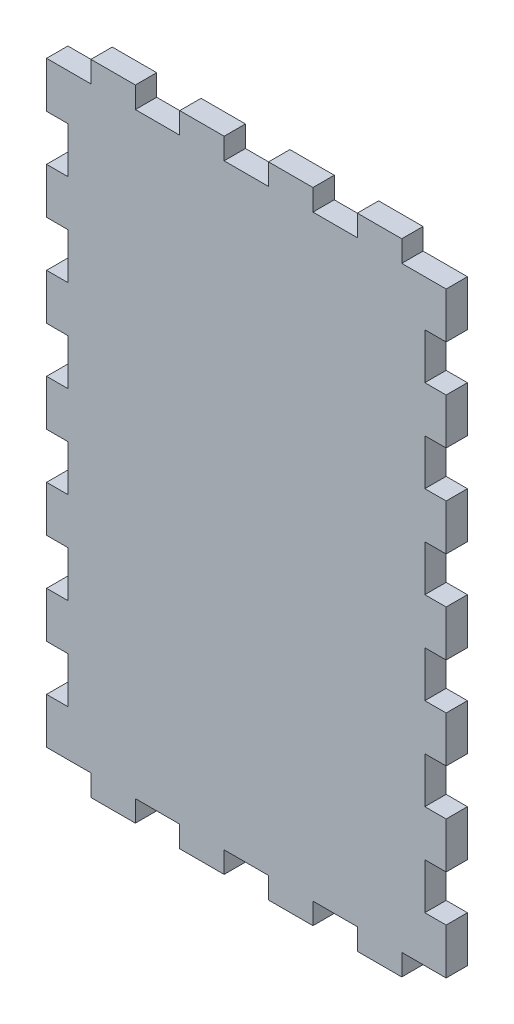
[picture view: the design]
ISO-10303-21;
HEADER;
FILE_DESCRIPTION(('STEP AP214'),'2;1');
FILE_NAME('part.step','',(''),(''),'','','');
FILE_SCHEMA(('AUTOMOTIVE_DESIGN { 1 0 10303 214 1 1 1 1 }'));
ENDSEC;
DATA;
#1=APPLICATION_CONTEXT('core data for automotive mechanical design processes');
#2=APPLICATION_PROTOCOL_DEFINITION('international standard','automotive_design',2000,#1);
#3=PRODUCT_CONTEXT('',#1,'mechanical');
#4=PRODUCT('Part','Part','',(#3));
#5=PRODUCT_RELATED_PRODUCT_CATEGORY('part','',(#4));
#6=PRODUCT_DEFINITION_FORMATION('','',#4);
#7=PRODUCT_DEFINITION_CONTEXT('part definition',#1,'design');
#8=PRODUCT_DEFINITION('design','',#6,#7);
#9=PRODUCT_DEFINITION_SHAPE('','',#8);
#10=(LENGTH_UNIT() NAMED_UNIT(*) SI_UNIT(.MILLI.,.METRE.));
#11=(NAMED_UNIT(*) PLANE_ANGLE_UNIT() SI_UNIT($,.RADIAN.));
#12=(NAMED_UNIT(*) SI_UNIT($,.STERADIAN.) SOLID_ANGLE_UNIT());
#13=UNCERTAINTY_MEASURE_WITH_UNIT(LENGTH_MEASURE(1.E-05),#10,'distance_accuracy_value','');
#14=(GEOMETRIC_REPRESENTATION_CONTEXT(3) GLOBAL_UNCERTAINTY_ASSIGNED_CONTEXT((#13)) GLOBAL_UNIT_ASSIGNED_CONTEXT((#10,
#11,#12)) REPRESENTATION_CONTEXT('',''));
#15=CARTESIAN_POINT('',(0.,0.,0.));
#16=DIRECTION('',(0.,0.,1.));
#17=DIRECTION('',(1.,0.,0.));
#18=AXIS2_PLACEMENT_3D('',#15,#16,#17);
#19=CARTESIAN_POINT('',(269.67,0.,4.));
#20=DIRECTION('',(-1.,0.,0.));
#21=DIRECTION('',(0.,0.,1.));
#22=AXIS2_PLACEMENT_3D('',#19,#20,#21);
#23=PLANE('',#22);
#24=DIRECTION('',(0.,1.,0.));
#25=VECTOR('',#24,1.);
#26=CARTESIAN_POINT('',(269.67,0.,0.));
#27=LINE('',#26,#25);
#28=CARTESIAN_POINT('',(269.67,79.,0.));
#29=VERTEX_POINT('',#28);
#30=CARTESIAN_POINT('',(269.67,83.,0.));
#31=VERTEX_POINT('',#30);
#32=EDGE_CURVE('E585',#29,#31,#27,.T.);
#33=ORIENTED_EDGE('',*,*,#32,.T.);
#34=DIRECTION('',(0.,0.,-1.));
#35=VECTOR('',#34,1.);
#36=CARTESIAN_POINT('',(269.67,83.,4.));
#37=LINE('',#36,#35);
#38=CARTESIAN_POINT('',(269.67,83.,4.));
#39=VERTEX_POINT('',#38);
#40=EDGE_CURVE('E11',#39,#31,#37,.T.);
#41=ORIENTED_EDGE('',*,*,#40,.F.);
#42=DIRECTION('',(0.,1.,0.));
#43=VECTOR('',#42,1.);
#44=CARTESIAN_POINT('',(269.67,0.,4.));
#45=LINE('',#44,#43);
#46=CARTESIAN_POINT('',(269.67,79.,4.));
#47=VERTEX_POINT('',#46);
#48=EDGE_CURVE('E751',#47,#39,#45,.T.);
#49=ORIENTED_EDGE('',*,*,#48,.F.);
#50=DIRECTION('',(0.,0.,-1.));
#51=VECTOR('',#50,1.);
#52=CARTESIAN_POINT('',(269.67,79.,4.));
#53=LINE('',#52,#51);
#54=EDGE_CURVE('E581',#47,#29,#53,.T.);
#55=ORIENTED_EDGE('',*,*,#54,.T.);
#56=EDGE_LOOP('',(#33,#41,#49,#55));
#57=FACE_BOUND('',#56,.T.);
#58=ADVANCED_FACE('F33',(#57),#23,.F.);
#59=CARTESIAN_POINT('',(0.,83.,4.));
#60=DIRECTION('',(0.,1.,0.));
#61=DIRECTION('',(0.,0.,1.));
#62=AXIS2_PLACEMENT_3D('',#59,#60,#61);
#63=PLANE('',#62);
#64=DIRECTION('',(1.,0.,0.));
#65=VECTOR('',#64,1.);
#66=CARTESIAN_POINT('',(0.,83.,0.));
#67=LINE('',#66,#65);
#68=CARTESIAN_POINT('',(278.,83.,0.));
#69=VERTEX_POINT('',#68);
#70=EDGE_CURVE('E588',#31,#69,#67,.T.);
#71=ORIENTED_EDGE('',*,*,#70,.T.);
#72=DIRECTION('',(0.,0.,-1.));
#73=VECTOR('',#72,1.);
#74=CARTESIAN_POINT('',(278.,83.,4.));
#75=LINE('',#74,#73);
#76=CARTESIAN_POINT('',(278.,83.,4.));
#77=VERTEX_POINT('',#76);
#78=EDGE_CURVE('E41',#77,#69,#75,.T.);
#79=ORIENTED_EDGE('',*,*,#78,.F.);
#80=DIRECTION('',(1.,0.,0.));
#81=VECTOR('',#80,1.);
#82=CARTESIAN_POINT('',(0.,83.,4.));
#83=LINE('',#82,#81);
#84=EDGE_CURVE('E320',#39,#77,#83,.T.);
#85=ORIENTED_EDGE('',*,*,#84,.F.);
#86=ORIENTED_EDGE('',*,*,#40,.T.);
#87=EDGE_LOOP('',(#71,#79,#85,#86));
#88=FACE_BOUND('',#87,.T.);
#89=ADVANCED_FACE('F1189',(#88),#63,.F.);
#90=CARTESIAN_POINT('',(278.,0.,4.));
#91=DIRECTION('',(-1.,0.,0.));
#92=DIRECTION('',(0.,0.,1.));
#93=AXIS2_PLACEMENT_3D('',#90,#91,#92);
#94=PLANE('',#93);
#95=DIRECTION('',(0.,1.,0.));
#96=VECTOR('',#95,1.);
#97=CARTESIAN_POINT('',(278.,0.,0.));
#98=LINE('',#97,#96);
#99=CARTESIAN_POINT('',(278.,91.61,0.));
#100=VERTEX_POINT('',#99);
#101=EDGE_CURVE('E590',#69,#100,#98,.T.);
#102=ORIENTED_EDGE('',*,*,#101,.T.);
#103=DIRECTION('',(0.,0.,-1.));
#104=VECTOR('',#103,1.);
#105=CARTESIAN_POINT('',(278.,91.61,4.));
#106=LINE('',#105,#104);
#107=CARTESIAN_POINT('',(278.,91.61,4.));
#108=VERTEX_POINT('',#107);
#109=EDGE_CURVE('E986',#108,#100,#106,.T.);
#110=ORIENTED_EDGE('',*,*,#109,.F.);
#111=DIRECTION('',(0.,1.,0.));
#112=VECTOR('',#111,1.);
#113=CARTESIAN_POINT('',(278.,0.,4.));
#114=LINE('',#113,#112);
#115=EDGE_CURVE('E994',#77,#108,#114,.T.);
#116=ORIENTED_EDGE('',*,*,#115,.F.);
#117=ORIENTED_EDGE('',*,*,#78,.T.);
#118=EDGE_LOOP('',(#102,#110,#116,#117));
#119=FACE_BOUND('',#118,.T.);
#120=ADVANCED_FACE('F992',(#119),#94,.F.);
#121=CARTESIAN_POINT('',(0.,91.61,4.));
#122=DIRECTION('',(0.,-1.,0.));
#123=DIRECTION('',(0.,0.,-1.));
#124=AXIS2_PLACEMENT_3D('',#121,#122,#123);
#125=PLANE('',#124);
#126=DIRECTION('',(-1.,0.,0.));
#127=VECTOR('',#126,1.);
#128=CARTESIAN_POINT('',(0.,91.61,0.));
#129=LINE('',#128,#127);
#130=CARTESIAN_POINT('',(274.,91.61,0.));
#131=VERTEX_POINT('',#130);
#132=EDGE_CURVE('E592',#100,#131,#129,.T.);
#133=ORIENTED_EDGE('',*,*,#132,.T.);
#134=DIRECTION('',(0.,0.,-1.));
#135=VECTOR('',#134,1.);
#136=CARTESIAN_POINT('',(274.,91.61,4.));
#137=LINE('',#136,#135);
#138=CARTESIAN_POINT('',(274.,91.61,4.));
#139=VERTEX_POINT('',#138);
#140=EDGE_CURVE('E983',#139,#131,#137,.T.);
#141=ORIENTED_EDGE('',*,*,#140,.F.);
#142=DIRECTION('',(-1.,0.,0.));
#143=VECTOR('',#142,1.);
#144=CARTESIAN_POINT('',(0.,91.61,4.));
#145=LINE('',#144,#143);
#146=EDGE_CURVE('E1012',#108,#139,#145,.T.);
#147=ORIENTED_EDGE('',*,*,#146,.F.);
#148=ORIENTED_EDGE('',*,*,#109,.T.);
#149=EDGE_LOOP('',(#133,#141,#147,#148));
#150=FACE_BOUND('',#149,.T.);
#151=ADVANCED_FACE('F1003',(#150),#125,.F.);
#152=CARTESIAN_POINT('',(274.,0.,4.));
#153=DIRECTION('',(-1.,0.,0.));
#154=DIRECTION('',(0.,0.,1.));
#155=AXIS2_PLACEMENT_3D('',#152,#153,#154);
#156=PLANE('',#155);
#157=DIRECTION('',(0.,1.,0.));
#158=VECTOR('',#157,1.);
#159=CARTESIAN_POINT('',(274.,0.,0.));
#160=LINE('',#159,#158);
#161=CARTESIAN_POINT('',(274.,100.23,0.));
#162=VERTEX_POINT('',#161);
#163=EDGE_CURVE('E594',#131,#162,#160,.T.);
#164=ORIENTED_EDGE('',*,*,#163,.T.);
#165=DIRECTION('',(0.,0.,-1.));
#166=VECTOR('',#165,1.);
#167=CARTESIAN_POINT('',(274.,100.23,4.));
#168=LINE('',#167,#166);
#169=CARTESIAN_POINT('',(274.,100.23,4.));
#170=VERTEX_POINT('',#169);
#171=EDGE_CURVE('E980',#170,#162,#168,.T.);
#172=ORIENTED_EDGE('',*,*,#171,.F.);
#173=DIRECTION('',(0.,1.,0.));
#174=VECTOR('',#173,1.);
#175=CARTESIAN_POINT('',(274.,0.,4.));
#176=LINE('',#175,#174);
#177=EDGE_CURVE('E1009',#139,#170,#176,.T.);
#178=ORIENTED_EDGE('',*,*,#177,.F.);
#179=ORIENTED_EDGE('',*,*,#140,.T.);
#180=EDGE_LOOP('',(#164,#172,#178,#179));
#181=FACE_BOUND('',#180,.T.);
#182=ADVANCED_FACE('F1007',(#181),#156,.F.);
#183=CARTESIAN_POINT('',(0.,100.23,4.));
#184=DIRECTION('',(0.,1.,0.));
#185=DIRECTION('',(0.,0.,1.));
#186=AXIS2_PLACEMENT_3D('',#183,#184,#185);
#187=PLANE('',#186);
#188=DIRECTION('',(1.,0.,0.));
#189=VECTOR('',#188,1.);
#190=CARTESIAN_POINT('',(0.,100.23,0.));
#191=LINE('',#190,#189);
#192=CARTESIAN_POINT('',(278.,100.23,0.));
#193=VERTEX_POINT('',#192);
#194=EDGE_CURVE('E596',#162,#193,#191,.T.);
#195=ORIENTED_EDGE('',*,*,#194,.T.);
#196=DIRECTION('',(0.,0.,-1.));
#197=VECTOR('',#196,1.);
#198=CARTESIAN_POINT('',(278.,100.23,4.));
#199=LINE('',#198,#197);
#200=CARTESIAN_POINT('',(278.,100.23,4.));
#201=VERTEX_POINT('',#200);
#202=EDGE_CURVE('E977',#201,#193,#199,.T.);
#203=ORIENTED_EDGE('',*,*,#202,.F.);
#204=DIRECTION('',(1.,0.,0.));
#205=VECTOR('',#204,1.);
#206=CARTESIAN_POINT('',(0.,100.23,4.));
#207=LINE('',#206,#205);
#208=EDGE_CURVE('E1011',#170,#201,#207,.T.);
#209=ORIENTED_EDGE('',*,*,#208,.F.);
#210=ORIENTED_EDGE('',*,*,#171,.T.);
#211=EDGE_LOOP('',(#195,#203,#209,#210));
#212=FACE_BOUND('',#211,.T.);
#213=ADVANCED_FACE('F1202',(#212),#187,.F.);
#214=CARTESIAN_POINT('',(278.,0.,4.));
#215=DIRECTION('',(-1.,0.,0.));
#216=DIRECTION('',(0.,0.,1.));
#217=AXIS2_PLACEMENT_3D('',#214,#215,#216);
#218=PLANE('',#217);
#219=DIRECTION('',(0.,1.,0.));
#220=VECTOR('',#219,1.);
#221=CARTESIAN_POINT('',(278.,0.,0.));
#222=LINE('',#221,#220);
#223=CARTESIAN_POINT('',(278.,108.85,0.));
#224=VERTEX_POINT('',#223);
#225=EDGE_CURVE('E598',#193,#224,#222,.T.);
#226=ORIENTED_EDGE('',*,*,#225,.T.);
#227=DIRECTION('',(0.,0.,-1.));
#228=VECTOR('',#227,1.);
#229=CARTESIAN_POINT('',(278.,108.85,4.));
#230=LINE('',#229,#228);
#231=CARTESIAN_POINT('',(278.,108.85,4.));
#232=VERTEX_POINT('',#231);
#233=EDGE_CURVE('E974',#232,#224,#230,.T.);
#234=ORIENTED_EDGE('',*,*,#233,.F.);
#235=DIRECTION('',(0.,1.,0.));
#236=VECTOR('',#235,1.);
#237=CARTESIAN_POINT('',(278.,0.,4.));
#238=LINE('',#237,#236);
#239=EDGE_CURVE('E1014',#201,#232,#238,.T.);
#240=ORIENTED_EDGE('',*,*,#239,.F.);
#241=ORIENTED_EDGE('',*,*,#202,.T.);
#242=EDGE_LOOP('',(#226,#234,#240,#241));
#243=FACE_BOUND('',#242,.T.);
#244=ADVANCED_FACE('F1205',(#243),#218,.F.);
#245=CARTESIAN_POINT('',(0.,108.85,4.));
#246=DIRECTION('',(0.,-1.,0.));
#247=DIRECTION('',(0.,0.,-1.));
#248=AXIS2_PLACEMENT_3D('',#245,#246,#247);
#249=PLANE('',#248);
#250=DIRECTION('',(-1.,0.,0.));
#251=VECTOR('',#250,1.);
#252=CARTESIAN_POINT('',(0.,108.85,0.));
#253=LINE('',#252,#251);
#254=CARTESIAN_POINT('',(274.,108.85,0.));
#255=VERTEX_POINT('',#254);
#256=EDGE_CURVE('E600',#224,#255,#253,.T.);
#257=ORIENTED_EDGE('',*,*,#256,.T.);
#258=DIRECTION('',(0.,0.,-1.));
#259=VECTOR('',#258,1.);
#260=CARTESIAN_POINT('',(274.,108.85,4.));
#261=LINE('',#260,#259);
#262=CARTESIAN_POINT('',(274.,108.85,4.));
#263=VERTEX_POINT('',#262);
#264=EDGE_CURVE('E971',#263,#255,#261,.T.);
#265=ORIENTED_EDGE('',*,*,#264,.F.);
#266=DIRECTION('',(-1.,0.,0.));
#267=VECTOR('',#266,1.);
#268=CARTESIAN_POINT('',(0.,108.85,4.));
#269=LINE('',#268,#267);
#270=EDGE_CURVE('E1020',#232,#263,#269,.T.);
#271=ORIENTED_EDGE('',*,*,#270,.F.);
#272=ORIENTED_EDGE('',*,*,#233,.T.);
#273=EDGE_LOOP('',(#257,#265,#271,#272));
#274=FACE_BOUND('',#273,.T.);
#275=ADVANCED_FACE('F1209',(#274),#249,.F.);
#276=CARTESIAN_POINT('',(274.,0.,4.));
#277=DIRECTION('',(-1.,0.,0.));
#278=DIRECTION('',(0.,0.,1.));
#279=AXIS2_PLACEMENT_3D('',#276,#277,#278);
#280=PLANE('',#279);
#281=DIRECTION('',(0.,1.,0.));
#282=VECTOR('',#281,1.);
#283=CARTESIAN_POINT('',(274.,0.,0.));
#284=LINE('',#283,#282);
#285=CARTESIAN_POINT('',(274.,117.46,0.));
#286=VERTEX_POINT('',#285);
#287=EDGE_CURVE('E602',#255,#286,#284,.T.);
#288=ORIENTED_EDGE('',*,*,#287,.T.);
#289=DIRECTION('',(0.,0.,-1.));
#290=VECTOR('',#289,1.);
#291=CARTESIAN_POINT('',(274.,117.46,4.));
#292=LINE('',#291,#290);
#293=CARTESIAN_POINT('',(274.,117.46,4.));
#294=VERTEX_POINT('',#293);
#295=EDGE_CURVE('E968',#294,#286,#292,.T.);
#296=ORIENTED_EDGE('',*,*,#295,.F.);
#297=DIRECTION('',(0.,1.,0.));
#298=VECTOR('',#297,1.);
#299=CARTESIAN_POINT('',(274.,0.,4.));
#300=LINE('',#299,#298);
#301=EDGE_CURVE('E1022',#263,#294,#300,.T.);
#302=ORIENTED_EDGE('',*,*,#301,.F.);
#303=ORIENTED_EDGE('',*,*,#264,.T.);
#304=EDGE_LOOP('',(#288,#296,#302,#303));
#305=FACE_BOUND('',#304,.T.);
#306=ADVANCED_FACE('F1213',(#305),#280,.F.);
#307=CARTESIAN_POINT('',(0.,117.46,4.));
#308=DIRECTION('',(0.,1.,0.));
#309=DIRECTION('',(0.,0.,1.));
#310=AXIS2_PLACEMENT_3D('',#307,#308,#309);
#311=PLANE('',#310);
#312=DIRECTION('',(1.,0.,0.));
#313=VECTOR('',#312,1.);
#314=CARTESIAN_POINT('',(0.,117.46,0.));
#315=LINE('',#314,#313);
#316=CARTESIAN_POINT('',(278.,117.46,0.));
#317=VERTEX_POINT('',#316);
#318=EDGE_CURVE('E604',#286,#317,#315,.T.);
#319=ORIENTED_EDGE('',*,*,#318,.T.);
#320=DIRECTION('',(0.,0.,-1.));
#321=VECTOR('',#320,1.);
#322=CARTESIAN_POINT('',(278.,117.46,4.));
#323=LINE('',#322,#321);
#324=CARTESIAN_POINT('',(278.,117.46,4.));
#325=VERTEX_POINT('',#324);
#326=EDGE_CURVE('E965',#325,#317,#323,.T.);
#327=ORIENTED_EDGE('',*,*,#326,.F.);
#328=DIRECTION('',(1.,0.,0.));
#329=VECTOR('',#328,1.);
#330=CARTESIAN_POINT('',(0.,117.46,4.));
#331=LINE('',#330,#329);
#332=EDGE_CURVE('E1024',#294,#325,#331,.T.);
#333=ORIENTED_EDGE('',*,*,#332,.F.);
#334=ORIENTED_EDGE('',*,*,#295,.T.);
#335=EDGE_LOOP('',(#319,#327,#333,#334));
#336=FACE_BOUND('',#335,.T.);
#337=ADVANCED_FACE('F1217',(#336),#311,.F.);
#338=CARTESIAN_POINT('',(278.,0.,4.));
#339=DIRECTION('',(-1.,0.,0.));
#340=DIRECTION('',(0.,0.,1.));
#341=AXIS2_PLACEMENT_3D('',#338,#339,#340);
#342=PLANE('',#341);
#343=DIRECTION('',(0.,1.,0.));
#344=VECTOR('',#343,1.);
#345=CARTESIAN_POINT('',(278.,0.,0.));
#346=LINE('',#345,#344);
#347=CARTESIAN_POINT('',(278.,126.08,0.));
#348=VERTEX_POINT('',#347);
#349=EDGE_CURVE('E606',#317,#348,#346,.T.);
#350=ORIENTED_EDGE('',*,*,#349,.T.);
#351=DIRECTION('',(0.,0.,-1.));
#352=VECTOR('',#351,1.);
#353=CARTESIAN_POINT('',(278.,126.08,4.));
#354=LINE('',#353,#352);
#355=CARTESIAN_POINT('',(278.,126.08,4.));
#356=VERTEX_POINT('',#355);
#357=EDGE_CURVE('E962',#356,#348,#354,.T.);
#358=ORIENTED_EDGE('',*,*,#357,.F.);
#359=DIRECTION('',(0.,1.,0.));
#360=VECTOR('',#359,1.);
#361=CARTESIAN_POINT('',(278.,0.,4.));
#362=LINE('',#361,#360);
#363=EDGE_CURVE('E1026',#325,#356,#362,.T.);
#364=ORIENTED_EDGE('',*,*,#363,.F.);
#365=ORIENTED_EDGE('',*,*,#326,.T.);
#366=EDGE_LOOP('',(#350,#358,#364,#365));
#367=FACE_BOUND('',#366,.T.);
#368=ADVANCED_FACE('F1221',(#367),#342,.F.);
#369=CARTESIAN_POINT('',(0.,126.08,4.));
#370=DIRECTION('',(0.,-1.,0.));
#371=DIRECTION('',(0.,0.,-1.));
#372=AXIS2_PLACEMENT_3D('',#369,#370,#371);
#373=PLANE('',#372);
#374=DIRECTION('',(-1.,0.,0.));
#375=VECTOR('',#374,1.);
#376=CARTESIAN_POINT('',(0.,126.08,0.));
#377=LINE('',#376,#375);
#378=CARTESIAN_POINT('',(274.,126.08,0.));
#379=VERTEX_POINT('',#378);
#380=EDGE_CURVE('E608',#348,#379,#377,.T.);
#381=ORIENTED_EDGE('',*,*,#380,.T.);
#382=DIRECTION('',(0.,0.,-1.));
#383=VECTOR('',#382,1.);
#384=CARTESIAN_POINT('',(274.,126.08,4.));
#385=LINE('',#384,#383);
#386=CARTESIAN_POINT('',(274.,126.08,4.));
#387=VERTEX_POINT('',#386);
#388=EDGE_CURVE('E959',#387,#379,#385,.T.);
#389=ORIENTED_EDGE('',*,*,#388,.F.);
#390=DIRECTION('',(-1.,0.,0.));
#391=VECTOR('',#390,1.);
#392=CARTESIAN_POINT('',(0.,126.08,4.));
#393=LINE('',#392,#391);
#394=EDGE_CURVE('E1028',#356,#387,#393,.T.);
#395=ORIENTED_EDGE('',*,*,#394,.F.);
#396=ORIENTED_EDGE('',*,*,#357,.T.);
#397=EDGE_LOOP('',(#381,#389,#395,#396));
#398=FACE_BOUND('',#397,.T.);
#399=ADVANCED_FACE('F1225',(#398),#373,.F.);
#400=CARTESIAN_POINT('',(274.,0.,4.));
#401=DIRECTION('',(-1.,0.,0.));
#402=DIRECTION('',(0.,0.,1.));
#403=AXIS2_PLACEMENT_3D('',#400,#401,#402);
#404=PLANE('',#403);
#405=DIRECTION('',(0.,1.,0.));
#406=VECTOR('',#405,1.);
#407=CARTESIAN_POINT('',(274.,0.,0.));
#408=LINE('',#407,#406);
#409=CARTESIAN_POINT('',(274.,134.69,0.));
#410=VERTEX_POINT('',#409);
#411=EDGE_CURVE('E610',#379,#410,#408,.T.);
#412=ORIENTED_EDGE('',*,*,#411,.T.);
#413=DIRECTION('',(0.,0.,-1.));
#414=VECTOR('',#413,1.);
#415=CARTESIAN_POINT('',(274.,134.69,4.));
#416=LINE('',#415,#414);
#417=CARTESIAN_POINT('',(274.,134.69,4.));
#418=VERTEX_POINT('',#417);
#419=EDGE_CURVE('E956',#418,#410,#416,.T.);
#420=ORIENTED_EDGE('',*,*,#419,.F.);
#421=DIRECTION('',(0.,1.,0.));
#422=VECTOR('',#421,1.);
#423=CARTESIAN_POINT('',(274.,0.,4.));
#424=LINE('',#423,#422);
#425=EDGE_CURVE('E1030',#387,#418,#424,.T.);
#426=ORIENTED_EDGE('',*,*,#425,.F.);
#427=ORIENTED_EDGE('',*,*,#388,.T.);
#428=EDGE_LOOP('',(#412,#420,#426,#427));
#429=FACE_BOUND('',#428,.T.);
#430=ADVANCED_FACE('F1229',(#429),#404,.F.);
#431=CARTESIAN_POINT('',(0.,134.69,4.));
#432=DIRECTION('',(0.,1.,0.));
#433=DIRECTION('',(0.,0.,1.));
#434=AXIS2_PLACEMENT_3D('',#431,#432,#433);
#435=PLANE('',#434);
#436=DIRECTION('',(1.,0.,0.));
#437=VECTOR('',#436,1.);
#438=CARTESIAN_POINT('',(0.,134.69,0.));
#439=LINE('',#438,#437);
#440=CARTESIAN_POINT('',(278.,134.69,0.));
#441=VERTEX_POINT('',#440);
#442=EDGE_CURVE('E612',#410,#441,#439,.T.);
#443=ORIENTED_EDGE('',*,*,#442,.T.);
#444=DIRECTION('',(0.,0.,-1.));
#445=VECTOR('',#444,1.);
#446=CARTESIAN_POINT('',(278.,134.69,4.));
#447=LINE('',#446,#445);
#448=CARTESIAN_POINT('',(278.,134.69,4.));
#449=VERTEX_POINT('',#448);
#450=EDGE_CURVE('E953',#449,#441,#447,.T.);
#451=ORIENTED_EDGE('',*,*,#450,.F.);
#452=DIRECTION('',(1.,0.,0.));
#453=VECTOR('',#452,1.);
#454=CARTESIAN_POINT('',(0.,134.69,4.));
#455=LINE('',#454,#453);
#456=EDGE_CURVE('E1032',#418,#449,#455,.T.);
#457=ORIENTED_EDGE('',*,*,#456,.F.);
#458=ORIENTED_EDGE('',*,*,#419,.T.);
#459=EDGE_LOOP('',(#443,#451,#457,#458));
#460=FACE_BOUND('',#459,.T.);
#461=ADVANCED_FACE('F1233',(#460),#435,.F.);
#462=CARTESIAN_POINT('',(278.,0.,4.));
#463=DIRECTION('',(-1.,0.,0.));
#464=DIRECTION('',(0.,0.,1.));
#465=AXIS2_PLACEMENT_3D('',#462,#463,#464);
#466=PLANE('',#465);
#467=DIRECTION('',(0.,1.,0.));
#468=VECTOR('',#467,1.);
#469=CARTESIAN_POINT('',(278.,0.,0.));
#470=LINE('',#469,#468);
#471=CARTESIAN_POINT('',(278.,143.31,0.));
#472=VERTEX_POINT('',#471);
#473=EDGE_CURVE('E614',#441,#472,#470,.T.);
#474=ORIENTED_EDGE('',*,*,#473,.T.);
#475=DIRECTION('',(0.,0.,-1.));
#476=VECTOR('',#475,1.);
#477=CARTESIAN_POINT('',(278.,143.31,4.));
#478=LINE('',#477,#476);
#479=CARTESIAN_POINT('',(278.,143.31,4.));
#480=VERTEX_POINT('',#479);
#481=EDGE_CURVE('E950',#480,#472,#478,.T.);
#482=ORIENTED_EDGE('',*,*,#481,.F.);
#483=DIRECTION('',(0.,1.,0.));
#484=VECTOR('',#483,1.);
#485=CARTESIAN_POINT('',(278.,0.,4.));
#486=LINE('',#485,#484);
#487=EDGE_CURVE('E1034',#449,#480,#486,.T.);
#488=ORIENTED_EDGE('',*,*,#487,.F.);
#489=ORIENTED_EDGE('',*,*,#450,.T.);
#490=EDGE_LOOP('',(#474,#482,#488,#489));
#491=FACE_BOUND('',#490,.T.);
#492=ADVANCED_FACE('F1237',(#491),#466,.F.);
#493=CARTESIAN_POINT('',(0.,143.31,4.));
#494=DIRECTION('',(0.,-1.,0.));
#495=DIRECTION('',(0.,0.,-1.));
#496=AXIS2_PLACEMENT_3D('',#493,#494,#495);
#497=PLANE('',#496);
#498=DIRECTION('',(-1.,0.,0.));
#499=VECTOR('',#498,1.);
#500=CARTESIAN_POINT('',(0.,143.31,0.));
#501=LINE('',#500,#499);
#502=CARTESIAN_POINT('',(274.,143.31,0.));
#503=VERTEX_POINT('',#502);
#504=EDGE_CURVE('E616',#472,#503,#501,.T.);
#505=ORIENTED_EDGE('',*,*,#504,.T.);
#506=DIRECTION('',(0.,0.,-1.));
#507=VECTOR('',#506,1.);
#508=CARTESIAN_POINT('',(274.,143.31,4.));
#509=LINE('',#508,#507);
#510=CARTESIAN_POINT('',(274.,143.31,4.));
#511=VERTEX_POINT('',#510);
#512=EDGE_CURVE('E947',#511,#503,#509,.T.);
#513=ORIENTED_EDGE('',*,*,#512,.F.);
#514=DIRECTION('',(-1.,0.,0.));
#515=VECTOR('',#514,1.);
#516=CARTESIAN_POINT('',(0.,143.31,4.));
#517=LINE('',#516,#515);
#518=EDGE_CURVE('E1036',#480,#511,#517,.T.);
#519=ORIENTED_EDGE('',*,*,#518,.F.);
#520=ORIENTED_EDGE('',*,*,#481,.T.);
#521=EDGE_LOOP('',(#505,#513,#519,#520));
#522=FACE_BOUND('',#521,.T.);
#523=ADVANCED_FACE('F1241',(#522),#497,.F.);
#524=CARTESIAN_POINT('',(274.,0.,4.));
#525=DIRECTION('',(-1.,0.,0.));
#526=DIRECTION('',(0.,0.,1.));
#527=AXIS2_PLACEMENT_3D('',#524,#525,#526);
#528=PLANE('',#527);
#529=DIRECTION('',(0.,1.,0.));
#530=VECTOR('',#529,1.);
#531=CARTESIAN_POINT('',(274.,0.,0.));
#532=LINE('',#531,#530);
#533=CARTESIAN_POINT('',(274.,151.92,0.));
#534=VERTEX_POINT('',#533);
#535=EDGE_CURVE('E618',#503,#534,#532,.T.);
#536=ORIENTED_EDGE('',*,*,#535,.T.);
#537=DIRECTION('',(0.,0.,-1.));
#538=VECTOR('',#537,1.);
#539=CARTESIAN_POINT('',(274.,151.92,4.));
#540=LINE('',#539,#538);
#541=CARTESIAN_POINT('',(274.,151.92,4.));
#542=VERTEX_POINT('',#541);
#543=EDGE_CURVE('E944',#542,#534,#540,.T.);
#544=ORIENTED_EDGE('',*,*,#543,.F.);
#545=DIRECTION('',(0.,1.,0.));
#546=VECTOR('',#545,1.);
#547=CARTESIAN_POINT('',(274.,0.,4.));
#548=LINE('',#547,#546);
#549=EDGE_CURVE('E1038',#511,#542,#548,.T.);
#550=ORIENTED_EDGE('',*,*,#549,.F.);
#551=ORIENTED_EDGE('',*,*,#512,.T.);
#552=EDGE_LOOP('',(#536,#544,#550,#551));
#553=FACE_BOUND('',#552,.T.);
#554=ADVANCED_FACE('F1245',(#553),#528,.F.);
#555=CARTESIAN_POINT('',(0.,151.92,4.));
#556=DIRECTION('',(0.,1.,0.));
#557=DIRECTION('',(0.,0.,1.));
#558=AXIS2_PLACEMENT_3D('',#555,#556,#557);
#559=PLANE('',#558);
#560=DIRECTION('',(1.,0.,0.));
#561=VECTOR('',#560,1.);
#562=CARTESIAN_POINT('',(0.,151.92,0.));
#563=LINE('',#562,#561);
#564=CARTESIAN_POINT('',(278.,151.92,0.));
#565=VERTEX_POINT('',#564);
#566=EDGE_CURVE('E620',#534,#565,#563,.T.);
#567=ORIENTED_EDGE('',*,*,#566,.T.);
#568=DIRECTION('',(0.,0.,-1.));
#569=VECTOR('',#568,1.);
#570=CARTESIAN_POINT('',(278.,151.92,4.));
#571=LINE('',#570,#569);
#572=CARTESIAN_POINT('',(278.,151.92,4.));
#573=VERTEX_POINT('',#572);
#574=EDGE_CURVE('E941',#573,#565,#571,.T.);
#575=ORIENTED_EDGE('',*,*,#574,.F.);
#576=DIRECTION('',(1.,0.,0.));
#577=VECTOR('',#576,1.);
#578=CARTESIAN_POINT('',(0.,151.92,4.));
#579=LINE('',#578,#577);
#580=EDGE_CURVE('E1040',#542,#573,#579,.T.);
#581=ORIENTED_EDGE('',*,*,#580,.F.);
#582=ORIENTED_EDGE('',*,*,#543,.T.);
#583=EDGE_LOOP('',(#567,#575,#581,#582));
#584=FACE_BOUND('',#583,.T.);
#585=ADVANCED_FACE('F1249',(#584),#559,.F.);
#586=CARTESIAN_POINT('',(278.,0.,4.));
#587=DIRECTION('',(-1.,0.,0.));
#588=DIRECTION('',(0.,0.,1.));
#589=AXIS2_PLACEMENT_3D('',#586,#587,#588);
#590=PLANE('',#589);
#591=DIRECTION('',(0.,1.,0.));
#592=VECTOR('',#591,1.);
#593=CARTESIAN_POINT('',(278.,0.,0.));
#594=LINE('',#593,#592);
#595=CARTESIAN_POINT('',(278.,160.54,0.));
#596=VERTEX_POINT('',#595);
#597=EDGE_CURVE('E622',#565,#596,#594,.T.);
#598=ORIENTED_EDGE('',*,*,#597,.T.);
#599=DIRECTION('',(0.,0.,-1.));
#600=VECTOR('',#599,1.);
#601=CARTESIAN_POINT('',(278.,160.54,4.));
#602=LINE('',#601,#600);
#603=CARTESIAN_POINT('',(278.,160.54,4.));
#604=VERTEX_POINT('',#603);
#605=EDGE_CURVE('E938',#604,#596,#602,.T.);
#606=ORIENTED_EDGE('',*,*,#605,.F.);
#607=DIRECTION('',(0.,1.,0.));
#608=VECTOR('',#607,1.);
#609=CARTESIAN_POINT('',(278.,0.,4.));
#610=LINE('',#609,#608);
#611=EDGE_CURVE('E1042',#573,#604,#610,.T.);
#612=ORIENTED_EDGE('',*,*,#611,.F.);
#613=ORIENTED_EDGE('',*,*,#574,.T.);
#614=EDGE_LOOP('',(#598,#606,#612,#613));
#615=FACE_BOUND('',#614,.T.);
#616=ADVANCED_FACE('F1253',(#615),#590,.F.);
#617=CARTESIAN_POINT('',(0.,160.54,4.));
#618=DIRECTION('',(0.,-1.,0.));
#619=DIRECTION('',(0.,0.,-1.));
#620=AXIS2_PLACEMENT_3D('',#617,#618,#619);
#621=PLANE('',#620);
#622=DIRECTION('',(-1.,0.,0.));
#623=VECTOR('',#622,1.);
#624=CARTESIAN_POINT('',(0.,160.54,0.));
#625=LINE('',#624,#623);
#626=CARTESIAN_POINT('',(274.,160.54,0.));
#627=VERTEX_POINT('',#626);
#628=EDGE_CURVE('E624',#596,#627,#625,.T.);
#629=ORIENTED_EDGE('',*,*,#628,.T.);
#630=DIRECTION('',(0.,0.,-1.));
#631=VECTOR('',#630,1.);
#632=CARTESIAN_POINT('',(274.,160.54,4.));
#633=LINE('',#632,#631);
#634=CARTESIAN_POINT('',(274.,160.54,4.));
#635=VERTEX_POINT('',#634);
#636=EDGE_CURVE('E935',#635,#627,#633,.T.);
#637=ORIENTED_EDGE('',*,*,#636,.F.);
#638=DIRECTION('',(-1.,0.,0.));
#639=VECTOR('',#638,1.);
#640=CARTESIAN_POINT('',(0.,160.54,4.));
#641=LINE('',#640,#639);
#642=EDGE_CURVE('E1044',#604,#635,#641,.T.);
#643=ORIENTED_EDGE('',*,*,#642,.F.);
#644=ORIENTED_EDGE('',*,*,#605,.T.);
#645=EDGE_LOOP('',(#629,#637,#643,#644));
#646=FACE_BOUND('',#645,.T.);
#647=ADVANCED_FACE('F1257',(#646),#621,.F.);
#648=CARTESIAN_POINT('',(274.,0.,4.));
#649=DIRECTION('',(-1.,0.,0.));
#650=DIRECTION('',(0.,0.,1.));
#651=AXIS2_PLACEMENT_3D('',#648,#649,#650);
#652=PLANE('',#651);
#653=DIRECTION('',(0.,1.,0.));
#654=VECTOR('',#653,1.);
#655=CARTESIAN_POINT('',(274.,0.,0.));
#656=LINE('',#655,#654);
#657=CARTESIAN_POINT('',(274.,169.15,0.));
#658=VERTEX_POINT('',#657);
#659=EDGE_CURVE('E626',#627,#658,#656,.T.);
#660=ORIENTED_EDGE('',*,*,#659,.T.);
#661=DIRECTION('',(0.,0.,-1.));
#662=VECTOR('',#661,1.);
#663=CARTESIAN_POINT('',(274.,169.15,4.));
#664=LINE('',#663,#662);
#665=CARTESIAN_POINT('',(274.,169.15,4.));
#666=VERTEX_POINT('',#665);
#667=EDGE_CURVE('E932',#666,#658,#664,.T.);
#668=ORIENTED_EDGE('',*,*,#667,.F.);
#669=DIRECTION('',(0.,1.,0.));
#670=VECTOR('',#669,1.);
#671=CARTESIAN_POINT('',(274.,0.,4.));
#672=LINE('',#671,#670);
#673=EDGE_CURVE('E1046',#635,#666,#672,.T.);
#674=ORIENTED_EDGE('',*,*,#673,.F.);
#675=ORIENTED_EDGE('',*,*,#636,.T.);
#676=EDGE_LOOP('',(#660,#668,#674,#675));
#677=FACE_BOUND('',#676,.T.);
#678=ADVANCED_FACE('F1261',(#677),#652,.F.);
#679=CARTESIAN_POINT('',(0.,169.15,4.));
#680=DIRECTION('',(0.,1.,0.));
#681=DIRECTION('',(0.,0.,1.));
#682=AXIS2_PLACEMENT_3D('',#679,#680,#681);
#683=PLANE('',#682);
#684=DIRECTION('',(1.,0.,0.));
#685=VECTOR('',#684,1.);
#686=CARTESIAN_POINT('',(0.,169.15,0.));
#687=LINE('',#686,#685);
#688=CARTESIAN_POINT('',(278.,169.15,0.));
#689=VERTEX_POINT('',#688);
#690=EDGE_CURVE('E628',#658,#689,#687,.T.);
#691=ORIENTED_EDGE('',*,*,#690,.T.);
#692=DIRECTION('',(0.,0.,-1.));
#693=VECTOR('',#692,1.);
#694=CARTESIAN_POINT('',(278.,169.15,4.));
#695=LINE('',#694,#693);
#696=CARTESIAN_POINT('',(278.,169.15,4.));
#697=VERTEX_POINT('',#696);
#698=EDGE_CURVE('E929',#697,#689,#695,.T.);
#699=ORIENTED_EDGE('',*,*,#698,.F.);
#700=DIRECTION('',(1.,0.,0.));
#701=VECTOR('',#700,1.);
#702=CARTESIAN_POINT('',(0.,169.15,4.));
#703=LINE('',#702,#701);
#704=EDGE_CURVE('E1048',#666,#697,#703,.T.);
#705=ORIENTED_EDGE('',*,*,#704,.F.);
#706=ORIENTED_EDGE('',*,*,#667,.T.);
#707=EDGE_LOOP('',(#691,#699,#705,#706));
#708=FACE_BOUND('',#707,.T.);
#709=ADVANCED_FACE('F1265',(#708),#683,.F.);
#710=CARTESIAN_POINT('',(278.,0.,4.));
#711=DIRECTION('',(-1.,0.,0.));
#712=DIRECTION('',(0.,0.,1.));
#713=AXIS2_PLACEMENT_3D('',#710,#711,#712);
#714=PLANE('',#713);
#715=DIRECTION('',(0.,1.,0.));
#716=VECTOR('',#715,1.);
#717=CARTESIAN_POINT('',(278.,0.,0.));
#718=LINE('',#717,#716);
#719=CARTESIAN_POINT('',(278.,177.77,0.));
#720=VERTEX_POINT('',#719);
#721=EDGE_CURVE('E630',#689,#720,#718,.T.);
#722=ORIENTED_EDGE('',*,*,#721,.T.);
#723=DIRECTION('',(0.,0.,-1.));
#724=VECTOR('',#723,1.);
#725=CARTESIAN_POINT('',(278.,177.77,4.));
#726=LINE('',#725,#724);
#727=CARTESIAN_POINT('',(278.,177.77,4.));
#728=VERTEX_POINT('',#727);
#729=EDGE_CURVE('E926',#728,#720,#726,.T.);
#730=ORIENTED_EDGE('',*,*,#729,.F.);
#731=DIRECTION('',(0.,1.,0.));
#732=VECTOR('',#731,1.);
#733=CARTESIAN_POINT('',(278.,0.,4.));
#734=LINE('',#733,#732);
#735=EDGE_CURVE('E1050',#697,#728,#734,.T.);
#736=ORIENTED_EDGE('',*,*,#735,.F.);
#737=ORIENTED_EDGE('',*,*,#698,.T.);
#738=EDGE_LOOP('',(#722,#730,#736,#737));
#739=FACE_BOUND('',#738,.T.);
#740=ADVANCED_FACE('F1269',(#739),#714,.F.);
#741=CARTESIAN_POINT('',(0.,177.77,4.));
#742=DIRECTION('',(0.,-1.,0.));
#743=DIRECTION('',(0.,0.,-1.));
#744=AXIS2_PLACEMENT_3D('',#741,#742,#743);
#745=PLANE('',#744);
#746=DIRECTION('',(-1.,0.,0.));
#747=VECTOR('',#746,1.);
#748=CARTESIAN_POINT('',(0.,177.77,0.));
#749=LINE('',#748,#747);
#750=CARTESIAN_POINT('',(274.,177.77,0.));
#751=VERTEX_POINT('',#750);
#752=EDGE_CURVE('E632',#720,#751,#749,.T.);
#753=ORIENTED_EDGE('',*,*,#752,.T.);
#754=DIRECTION('',(0.,0.,-1.));
#755=VECTOR('',#754,1.);
#756=CARTESIAN_POINT('',(274.,177.77,4.));
#757=LINE('',#756,#755);
#758=CARTESIAN_POINT('',(274.,177.77,4.));
#759=VERTEX_POINT('',#758);
#760=EDGE_CURVE('E923',#759,#751,#757,.T.);
#761=ORIENTED_EDGE('',*,*,#760,.F.);
#762=DIRECTION('',(-1.,0.,0.));
#763=VECTOR('',#762,1.);
#764=CARTESIAN_POINT('',(0.,177.77,4.));
#765=LINE('',#764,#763);
#766=EDGE_CURVE('E1052',#728,#759,#765,.T.);
#767=ORIENTED_EDGE('',*,*,#766,.F.);
#768=ORIENTED_EDGE('',*,*,#729,.T.);
#769=EDGE_LOOP('',(#753,#761,#767,#768));
#770=FACE_BOUND('',#769,.T.);
#771=ADVANCED_FACE('F1273',(#770),#745,.F.);
#772=CARTESIAN_POINT('',(274.,0.,4.));
#773=DIRECTION('',(-1.,0.,0.));
#774=DIRECTION('',(0.,0.,1.));
#775=AXIS2_PLACEMENT_3D('',#772,#773,#774);
#776=PLANE('',#775);
#777=DIRECTION('',(0.,1.,0.));
#778=VECTOR('',#777,1.);
#779=CARTESIAN_POINT('',(274.,0.,0.));
#780=LINE('',#779,#778);
#781=CARTESIAN_POINT('',(274.,186.38,0.));
#782=VERTEX_POINT('',#781);
#783=EDGE_CURVE('E634',#751,#782,#780,.T.);
#784=ORIENTED_EDGE('',*,*,#783,.T.);
#785=DIRECTION('',(0.,0.,-1.));
#786=VECTOR('',#785,1.);
#787=CARTESIAN_POINT('',(274.,186.38,4.));
#788=LINE('',#787,#786);
#789=CARTESIAN_POINT('',(274.,186.38,4.));
#790=VERTEX_POINT('',#789);
#791=EDGE_CURVE('E920',#790,#782,#788,.T.);
#792=ORIENTED_EDGE('',*,*,#791,.F.);
#793=DIRECTION('',(0.,1.,0.));
#794=VECTOR('',#793,1.);
#795=CARTESIAN_POINT('',(274.,0.,4.));
#796=LINE('',#795,#794);
#797=EDGE_CURVE('E1054',#759,#790,#796,.T.);
#798=ORIENTED_EDGE('',*,*,#797,.F.);
#799=ORIENTED_EDGE('',*,*,#760,.T.);
#800=EDGE_LOOP('',(#784,#792,#798,#799));
#801=FACE_BOUND('',#800,.T.);
#802=ADVANCED_FACE('F1277',(#801),#776,.F.);
#803=CARTESIAN_POINT('',(0.,186.38,4.));
#804=DIRECTION('',(0.,1.,0.));
#805=DIRECTION('',(0.,0.,1.));
#806=AXIS2_PLACEMENT_3D('',#803,#804,#805);
#807=PLANE('',#806);
#808=DIRECTION('',(1.,0.,0.));
#809=VECTOR('',#808,1.);
#810=CARTESIAN_POINT('',(0.,186.38,0.));
#811=LINE('',#810,#809);
#812=CARTESIAN_POINT('',(278.,186.38,0.));
#813=VERTEX_POINT('',#812);
#814=EDGE_CURVE('E636',#782,#813,#811,.T.);
#815=ORIENTED_EDGE('',*,*,#814,.T.);
#816=DIRECTION('',(0.,0.,-1.));
#817=VECTOR('',#816,1.);
#818=CARTESIAN_POINT('',(278.,186.38,4.));
#819=LINE('',#818,#817);
#820=CARTESIAN_POINT('',(278.,186.38,4.));
#821=VERTEX_POINT('',#820);
#822=EDGE_CURVE('E917',#821,#813,#819,.T.);
#823=ORIENTED_EDGE('',*,*,#822,.F.);
#824=DIRECTION('',(1.,0.,0.));
#825=VECTOR('',#824,1.);
#826=CARTESIAN_POINT('',(0.,186.38,4.));
#827=LINE('',#826,#825);
#828=EDGE_CURVE('E1056',#790,#821,#827,.T.);
#829=ORIENTED_EDGE('',*,*,#828,.F.);
#830=ORIENTED_EDGE('',*,*,#791,.T.);
#831=EDGE_LOOP('',(#815,#823,#829,#830));
#832=FACE_BOUND('',#831,.T.);
#833=ADVANCED_FACE('F1281',(#832),#807,.F.);
#834=CARTESIAN_POINT('',(278.,0.,4.));
#835=DIRECTION('',(-1.,0.,0.));
#836=DIRECTION('',(0.,0.,1.));
#837=AXIS2_PLACEMENT_3D('',#834,#835,#836);
#838=PLANE('',#837);
#839=DIRECTION('',(0.,1.,0.));
#840=VECTOR('',#839,1.);
#841=CARTESIAN_POINT('',(278.,0.,0.));
#842=LINE('',#841,#840);
#843=CARTESIAN_POINT('',(278.,195.,0.));
#844=VERTEX_POINT('',#843);
#845=EDGE_CURVE('E638',#813,#844,#842,.T.);
#846=ORIENTED_EDGE('',*,*,#845,.T.);
#847=DIRECTION('',(0.,0.,-1.));
#848=VECTOR('',#847,1.);
#849=CARTESIAN_POINT('',(278.,195.,4.));
#850=LINE('',#849,#848);
#851=CARTESIAN_POINT('',(278.,195.,4.));
#852=VERTEX_POINT('',#851);
#853=EDGE_CURVE('E914',#852,#844,#850,.T.);
#854=ORIENTED_EDGE('',*,*,#853,.F.);
#855=DIRECTION('',(0.,1.,0.));
#856=VECTOR('',#855,1.);
#857=CARTESIAN_POINT('',(278.,0.,4.));
#858=LINE('',#857,#856);
#859=EDGE_CURVE('E1058',#821,#852,#858,.T.);
#860=ORIENTED_EDGE('',*,*,#859,.F.);
#861=ORIENTED_EDGE('',*,*,#822,.T.);
#862=EDGE_LOOP('',(#846,#854,#860,#861));
#863=FACE_BOUND('',#862,.T.);
#864=ADVANCED_FACE('F1285',(#863),#838,.F.);
#865=CARTESIAN_POINT('',(0.,195.,4.));
#866=DIRECTION('',(0.,-1.,0.));
#867=DIRECTION('',(0.,0.,-1.));
#868=AXIS2_PLACEMENT_3D('',#865,#866,#867);
#869=PLANE('',#868);
#870=DIRECTION('',(-1.,0.,0.));
#871=VECTOR('',#870,1.);
#872=CARTESIAN_POINT('',(0.,195.,0.));
#873=LINE('',#872,#871);
#874=CARTESIAN_POINT('',(269.67,195.,0.));
#875=VERTEX_POINT('',#874);
#876=EDGE_CURVE('E640',#844,#875,#873,.T.);
#877=ORIENTED_EDGE('',*,*,#876,.T.);
#878=DIRECTION('',(0.,0.,-1.));
#879=VECTOR('',#878,1.);
#880=CARTESIAN_POINT('',(269.67,195.,4.));
#881=LINE('',#880,#879);
#882=CARTESIAN_POINT('',(269.67,195.,4.));
#883=VERTEX_POINT('',#882);
#884=EDGE_CURVE('E911',#883,#875,#881,.T.);
#885=ORIENTED_EDGE('',*,*,#884,.F.);
#886=DIRECTION('',(-1.,0.,0.));
#887=VECTOR('',#886,1.);
#888=CARTESIAN_POINT('',(0.,195.,4.));
#889=LINE('',#888,#887);
#890=EDGE_CURVE('E1060',#852,#883,#889,.T.);
#891=ORIENTED_EDGE('',*,*,#890,.F.);
#892=ORIENTED_EDGE('',*,*,#853,.T.);
#893=EDGE_LOOP('',(#877,#885,#891,#892));
#894=FACE_BOUND('',#893,.T.);
#895=ADVANCED_FACE('F1289',(#894),#869,.F.);
#896=CARTESIAN_POINT('',(269.67,0.,4.));
#897=DIRECTION('',(-1.,0.,0.));
#898=DIRECTION('',(0.,0.,1.));
#899=AXIS2_PLACEMENT_3D('',#896,#897,#898);
#900=PLANE('',#899);
#901=DIRECTION('',(0.,1.,0.));
#902=VECTOR('',#901,1.);
#903=CARTESIAN_POINT('',(269.67,0.,0.));
#904=LINE('',#903,#902);
#905=CARTESIAN_POINT('',(269.67,199.,0.));
#906=VERTEX_POINT('',#905);
#907=EDGE_CURVE('E642',#875,#906,#904,.T.);
#908=ORIENTED_EDGE('',*,*,#907,.T.);
#909=DIRECTION('',(0.,0.,-1.));
#910=VECTOR('',#909,1.);
#911=CARTESIAN_POINT('',(269.67,199.,4.));
#912=LINE('',#911,#910);
#913=CARTESIAN_POINT('',(269.67,199.,4.));
#914=VERTEX_POINT('',#913);
#915=EDGE_CURVE('E908',#914,#906,#912,.T.);
#916=ORIENTED_EDGE('',*,*,#915,.F.);
#917=DIRECTION('',(0.,1.,0.));
#918=VECTOR('',#917,1.);
#919=CARTESIAN_POINT('',(269.67,0.,4.));
#920=LINE('',#919,#918);
#921=EDGE_CURVE('E1062',#883,#914,#920,.T.);
#922=ORIENTED_EDGE('',*,*,#921,.F.);
#923=ORIENTED_EDGE('',*,*,#884,.T.);
#924=EDGE_LOOP('',(#908,#916,#922,#923));
#925=FACE_BOUND('',#924,.T.);
#926=ADVANCED_FACE('F1293',(#925),#900,.F.);
#927=CARTESIAN_POINT('',(0.,199.,4.));
#928=DIRECTION('',(0.,-1.,0.));
#929=DIRECTION('',(0.,0.,-1.));
#930=AXIS2_PLACEMENT_3D('',#927,#928,#929);
#931=PLANE('',#930);
#932=DIRECTION('',(-1.,0.,0.));
#933=VECTOR('',#932,1.);
#934=CARTESIAN_POINT('',(0.,199.,0.));
#935=LINE('',#934,#933);
#936=CARTESIAN_POINT('',(261.33,199.,0.));
#937=VERTEX_POINT('',#936);
#938=EDGE_CURVE('E644',#906,#937,#935,.T.);
#939=ORIENTED_EDGE('',*,*,#938,.T.);
#940=DIRECTION('',(0.,0.,-1.));
#941=VECTOR('',#940,1.);
#942=CARTESIAN_POINT('',(261.33,199.,4.));
#943=LINE('',#942,#941);
#944=CARTESIAN_POINT('',(261.33,199.,4.));
#945=VERTEX_POINT('',#944);
#946=EDGE_CURVE('E905',#945,#937,#943,.T.);
#947=ORIENTED_EDGE('',*,*,#946,.F.);
#948=DIRECTION('',(-1.,0.,0.));
#949=VECTOR('',#948,1.);
#950=CARTESIAN_POINT('',(0.,199.,4.));
#951=LINE('',#950,#949);
#952=EDGE_CURVE('E1064',#914,#945,#951,.T.);
#953=ORIENTED_EDGE('',*,*,#952,.F.);
#954=ORIENTED_EDGE('',*,*,#915,.T.);
#955=EDGE_LOOP('',(#939,#947,#953,#954));
#956=FACE_BOUND('',#955,.T.);
#957=ADVANCED_FACE('F1297',(#956),#931,.F.);
#958=CARTESIAN_POINT('',(261.33,0.,4.));
#959=DIRECTION('',(1.,0.,0.));
#960=DIRECTION('',(0.,0.,-1.));
#961=AXIS2_PLACEMENT_3D('',#958,#959,#960);
#962=PLANE('',#961);
#963=DIRECTION('',(0.,-1.,0.));
#964=VECTOR('',#963,1.);
#965=CARTESIAN_POINT('',(261.33,0.,0.));
#966=LINE('',#965,#964);
#967=CARTESIAN_POINT('',(261.33,195.,0.));
#968=VERTEX_POINT('',#967);
#969=EDGE_CURVE('E646',#937,#968,#966,.T.);
#970=ORIENTED_EDGE('',*,*,#969,.T.);
#971=DIRECTION('',(0.,0.,-1.));
#972=VECTOR('',#971,1.);
#973=CARTESIAN_POINT('',(261.33,195.,4.));
#974=LINE('',#973,#972);
#975=CARTESIAN_POINT('',(261.33,195.,4.));
#976=VERTEX_POINT('',#975);
#977=EDGE_CURVE('E902',#976,#968,#974,.T.);
#978=ORIENTED_EDGE('',*,*,#977,.F.);
#979=DIRECTION('',(0.,-1.,0.));
#980=VECTOR('',#979,1.);
#981=CARTESIAN_POINT('',(261.33,0.,4.));
#982=LINE('',#981,#980);
#983=EDGE_CURVE('E1066',#945,#976,#982,.T.);
#984=ORIENTED_EDGE('',*,*,#983,.F.);
#985=ORIENTED_EDGE('',*,*,#946,.T.);
#986=EDGE_LOOP('',(#970,#978,#984,#985));
#987=FACE_BOUND('',#986,.T.);
#988=ADVANCED_FACE('F1301',(#987),#962,.F.);
#989=CARTESIAN_POINT('',(0.,195.,4.));
#990=DIRECTION('',(0.,-1.,0.));
#991=DIRECTION('',(0.,0.,-1.));
#992=AXIS2_PLACEMENT_3D('',#989,#990,#991);
#993=PLANE('',#992);
#994=DIRECTION('',(-1.,0.,0.));
#995=VECTOR('',#994,1.);
#996=CARTESIAN_POINT('',(0.,195.,0.));
#997=LINE('',#996,#995);
#998=CARTESIAN_POINT('',(253.,195.,0.));
#999=VERTEX_POINT('',#998);
#1000=EDGE_CURVE('E648',#968,#999,#997,.T.);
#1001=ORIENTED_EDGE('',*,*,#1000,.T.);
#1002=DIRECTION('',(0.,0.,-1.));
#1003=VECTOR('',#1002,1.);
#1004=CARTESIAN_POINT('',(253.,195.,4.));
#1005=LINE('',#1004,#1003);
#1006=CARTESIAN_POINT('',(253.,195.,4.));
#1007=VERTEX_POINT('',#1006);
#1008=EDGE_CURVE('E899',#1007,#999,#1005,.T.);
#1009=ORIENTED_EDGE('',*,*,#1008,.F.);
#1010=DIRECTION('',(-1.,0.,0.));
#1011=VECTOR('',#1010,1.);
#1012=CARTESIAN_POINT('',(0.,195.,4.));
#1013=LINE('',#1012,#1011);
#1014=EDGE_CURVE('E1068',#976,#1007,#1013,.T.);
#1015=ORIENTED_EDGE('',*,*,#1014,.F.);
#1016=ORIENTED_EDGE('',*,*,#977,.T.);
#1017=EDGE_LOOP('',(#1001,#1009,#1015,#1016));
#1018=FACE_BOUND('',#1017,.T.);
#1019=ADVANCED_FACE('F1305',(#1018),#993,.F.);
#1020=CARTESIAN_POINT('',(253.,0.,4.));
#1021=DIRECTION('',(-1.,0.,0.));
#1022=DIRECTION('',(0.,0.,1.));
#1023=AXIS2_PLACEMENT_3D('',#1020,#1021,#1022);
#1024=PLANE('',#1023);
#1025=DIRECTION('',(0.,1.,0.));
#1026=VECTOR('',#1025,1.);
#1027=CARTESIAN_POINT('',(253.,0.,0.));
#1028=LINE('',#1027,#1026);
#1029=CARTESIAN_POINT('',(253.,199.,0.));
#1030=VERTEX_POINT('',#1029);
#1031=EDGE_CURVE('E650',#999,#1030,#1028,.T.);
#1032=ORIENTED_EDGE('',*,*,#1031,.T.);
#1033=DIRECTION('',(0.,0.,-1.));
#1034=VECTOR('',#1033,1.);
#1035=CARTESIAN_POINT('',(253.,199.,4.));
#1036=LINE('',#1035,#1034);
#1037=CARTESIAN_POINT('',(253.,199.,4.));
#1038=VERTEX_POINT('',#1037);
#1039=EDGE_CURVE('E896',#1038,#1030,#1036,.T.);
#1040=ORIENTED_EDGE('',*,*,#1039,.F.);
#1041=DIRECTION('',(0.,1.,0.));
#1042=VECTOR('',#1041,1.);
#1043=CARTESIAN_POINT('',(253.,0.,4.));
#1044=LINE('',#1043,#1042);
#1045=EDGE_CURVE('E1070',#1007,#1038,#1044,.T.);
#1046=ORIENTED_EDGE('',*,*,#1045,.F.);
#1047=ORIENTED_EDGE('',*,*,#1008,.T.);
#1048=EDGE_LOOP('',(#1032,#1040,#1046,#1047));
#1049=FACE_BOUND('',#1048,.T.);
#1050=ADVANCED_FACE('F1309',(#1049),#1024,.F.);
#1051=CARTESIAN_POINT('',(0.,199.,4.));
#1052=DIRECTION('',(0.,-1.,0.));
#1053=DIRECTION('',(0.,0.,-1.));
#1054=AXIS2_PLACEMENT_3D('',#1051,#1052,#1053);
#1055=PLANE('',#1054);
#1056=DIRECTION('',(-1.,0.,0.));
#1057=VECTOR('',#1056,1.);
#1058=CARTESIAN_POINT('',(0.,199.,0.));
#1059=LINE('',#1058,#1057);
#1060=CARTESIAN_POINT('',(244.67,199.,0.));
#1061=VERTEX_POINT('',#1060);
#1062=EDGE_CURVE('E652',#1030,#1061,#1059,.T.);
#1063=ORIENTED_EDGE('',*,*,#1062,.T.);
#1064=DIRECTION('',(0.,0.,-1.));
#1065=VECTOR('',#1064,1.);
#1066=CARTESIAN_POINT('',(244.67,199.,4.));
#1067=LINE('',#1066,#1065);
#1068=CARTESIAN_POINT('',(244.67,199.,4.));
#1069=VERTEX_POINT('',#1068);
#1070=EDGE_CURVE('E893',#1069,#1061,#1067,.T.);
#1071=ORIENTED_EDGE('',*,*,#1070,.F.);
#1072=DIRECTION('',(-1.,0.,0.));
#1073=VECTOR('',#1072,1.);
#1074=CARTESIAN_POINT('',(0.,199.,4.));
#1075=LINE('',#1074,#1073);
#1076=EDGE_CURVE('E1072',#1038,#1069,#1075,.T.);
#1077=ORIENTED_EDGE('',*,*,#1076,.F.);
#1078=ORIENTED_EDGE('',*,*,#1039,.T.);
#1079=EDGE_LOOP('',(#1063,#1071,#1077,#1078));
#1080=FACE_BOUND('',#1079,.T.);
#1081=ADVANCED_FACE('F1313',(#1080),#1055,.F.);
#1082=CARTESIAN_POINT('',(244.67,0.,4.));
#1083=DIRECTION('',(1.,0.,0.));
#1084=DIRECTION('',(0.,0.,-1.));
#1085=AXIS2_PLACEMENT_3D('',#1082,#1083,#1084);
#1086=PLANE('',#1085);
#1087=DIRECTION('',(0.,-1.,0.));
#1088=VECTOR('',#1087,1.);
#1089=CARTESIAN_POINT('',(244.67,0.,0.));
#1090=LINE('',#1089,#1088);
#1091=CARTESIAN_POINT('',(244.67,195.,0.));
#1092=VERTEX_POINT('',#1091);
#1093=EDGE_CURVE('E654',#1061,#1092,#1090,.T.);
#1094=ORIENTED_EDGE('',*,*,#1093,.T.);
#1095=DIRECTION('',(0.,0.,-1.));
#1096=VECTOR('',#1095,1.);
#1097=CARTESIAN_POINT('',(244.67,195.,4.));
#1098=LINE('',#1097,#1096);
#1099=CARTESIAN_POINT('',(244.67,195.,4.));
#1100=VERTEX_POINT('',#1099);
#1101=EDGE_CURVE('E890',#1100,#1092,#1098,.T.);
#1102=ORIENTED_EDGE('',*,*,#1101,.F.);
#1103=DIRECTION('',(0.,-1.,0.));
#1104=VECTOR('',#1103,1.);
#1105=CARTESIAN_POINT('',(244.67,0.,4.));
#1106=LINE('',#1105,#1104);
#1107=EDGE_CURVE('E1074',#1069,#1100,#1106,.T.);
#1108=ORIENTED_EDGE('',*,*,#1107,.F.);
#1109=ORIENTED_EDGE('',*,*,#1070,.T.);
#1110=EDGE_LOOP('',(#1094,#1102,#1108,#1109));
#1111=FACE_BOUND('',#1110,.T.);
#1112=ADVANCED_FACE('F1317',(#1111),#1086,.F.);
#1113=CARTESIAN_POINT('',(0.,195.,4.));
#1114=DIRECTION('',(0.,-1.,0.));
#1115=DIRECTION('',(0.,0.,-1.));
#1116=AXIS2_PLACEMENT_3D('',#1113,#1114,#1115);
#1117=PLANE('',#1116);
#1118=DIRECTION('',(-1.,0.,0.));
#1119=VECTOR('',#1118,1.);
#1120=CARTESIAN_POINT('',(0.,195.,0.));
#1121=LINE('',#1120,#1119);
#1122=CARTESIAN_POINT('',(236.33,195.,0.));
#1123=VERTEX_POINT('',#1122);
#1124=EDGE_CURVE('E656',#1092,#1123,#1121,.T.);
#1125=ORIENTED_EDGE('',*,*,#1124,.T.);
#1126=DIRECTION('',(0.,0.,-1.));
#1127=VECTOR('',#1126,1.);
#1128=CARTESIAN_POINT('',(236.33,195.,4.));
#1129=LINE('',#1128,#1127);
#1130=CARTESIAN_POINT('',(236.33,195.,4.));
#1131=VERTEX_POINT('',#1130);
#1132=EDGE_CURVE('E887',#1131,#1123,#1129,.T.);
#1133=ORIENTED_EDGE('',*,*,#1132,.F.);
#1134=DIRECTION('',(-1.,0.,0.));
#1135=VECTOR('',#1134,1.);
#1136=CARTESIAN_POINT('',(0.,195.,4.));
#1137=LINE('',#1136,#1135);
#1138=EDGE_CURVE('E1076',#1100,#1131,#1137,.T.);
#1139=ORIENTED_EDGE('',*,*,#1138,.F.);
#1140=ORIENTED_EDGE('',*,*,#1101,.T.);
#1141=EDGE_LOOP('',(#1125,#1133,#1139,#1140));
#1142=FACE_BOUND('',#1141,.T.);
#1143=ADVANCED_FACE('F1321',(#1142),#1117,.F.);
#1144=CARTESIAN_POINT('',(236.33,0.,4.));
#1145=DIRECTION('',(-1.,0.,0.));
#1146=DIRECTION('',(0.,0.,1.));
#1147=AXIS2_PLACEMENT_3D('',#1144,#1145,#1146);
#1148=PLANE('',#1147);
#1149=DIRECTION('',(0.,1.,0.));
#1150=VECTOR('',#1149,1.);
#1151=CARTESIAN_POINT('',(236.33,0.,0.));
#1152=LINE('',#1151,#1150);
#1153=CARTESIAN_POINT('',(236.33,199.,0.));
#1154=VERTEX_POINT('',#1153);
#1155=EDGE_CURVE('E658',#1123,#1154,#1152,.T.);
#1156=ORIENTED_EDGE('',*,*,#1155,.T.);
#1157=DIRECTION('',(0.,0.,-1.));
#1158=VECTOR('',#1157,1.);
#1159=CARTESIAN_POINT('',(236.33,199.,4.));
#1160=LINE('',#1159,#1158);
#1161=CARTESIAN_POINT('',(236.33,199.,4.));
#1162=VERTEX_POINT('',#1161);
#1163=EDGE_CURVE('E884',#1162,#1154,#1160,.T.);
#1164=ORIENTED_EDGE('',*,*,#1163,.F.);
#1165=DIRECTION('',(0.,1.,0.));
#1166=VECTOR('',#1165,1.);
#1167=CARTESIAN_POINT('',(236.33,0.,4.));
#1168=LINE('',#1167,#1166);
#1169=EDGE_CURVE('E1078',#1131,#1162,#1168,.T.);
#1170=ORIENTED_EDGE('',*,*,#1169,.F.);
#1171=ORIENTED_EDGE('',*,*,#1132,.T.);
#1172=EDGE_LOOP('',(#1156,#1164,#1170,#1171));
#1173=FACE_BOUND('',#1172,.T.);
#1174=ADVANCED_FACE('F1325',(#1173),#1148,.F.);
#1175=CARTESIAN_POINT('',(0.,199.,4.));
#1176=DIRECTION('',(0.,-1.,0.));
#1177=DIRECTION('',(0.,0.,-1.));
#1178=AXIS2_PLACEMENT_3D('',#1175,#1176,#1177);
#1179=PLANE('',#1178);
#1180=DIRECTION('',(-1.,0.,0.));
#1181=VECTOR('',#1180,1.);
#1182=CARTESIAN_POINT('',(0.,199.,0.));
#1183=LINE('',#1182,#1181);
#1184=CARTESIAN_POINT('',(228.,199.,0.));
#1185=VERTEX_POINT('',#1184);
#1186=EDGE_CURVE('E660',#1154,#1185,#1183,.T.);
#1187=ORIENTED_EDGE('',*,*,#1186,.T.);
#1188=DIRECTION('',(0.,0.,-1.));
#1189=VECTOR('',#1188,1.);
#1190=CARTESIAN_POINT('',(228.,199.,4.));
#1191=LINE('',#1190,#1189);
#1192=CARTESIAN_POINT('',(228.,199.,4.));
#1193=VERTEX_POINT('',#1192);
#1194=EDGE_CURVE('E881',#1193,#1185,#1191,.T.);
#1195=ORIENTED_EDGE('',*,*,#1194,.F.);
#1196=DIRECTION('',(-1.,0.,0.));
#1197=VECTOR('',#1196,1.);
#1198=CARTESIAN_POINT('',(0.,199.,4.));
#1199=LINE('',#1198,#1197);
#1200=EDGE_CURVE('E1080',#1162,#1193,#1199,.T.);
#1201=ORIENTED_EDGE('',*,*,#1200,.F.);
#1202=ORIENTED_EDGE('',*,*,#1163,.T.);
#1203=EDGE_LOOP('',(#1187,#1195,#1201,#1202));
#1204=FACE_BOUND('',#1203,.T.);
#1205=ADVANCED_FACE('F1329',(#1204),#1179,.F.);
#1206=CARTESIAN_POINT('',(228.,0.,4.));
#1207=DIRECTION('',(1.,0.,0.));
#1208=DIRECTION('',(0.,0.,-1.));
#1209=AXIS2_PLACEMENT_3D('',#1206,#1207,#1208);
#1210=PLANE('',#1209);
#1211=DIRECTION('',(0.,-1.,0.));
#1212=VECTOR('',#1211,1.);
#1213=CARTESIAN_POINT('',(228.,0.,0.));
#1214=LINE('',#1213,#1212);
#1215=CARTESIAN_POINT('',(228.,195.,0.));
#1216=VERTEX_POINT('',#1215);
#1217=EDGE_CURVE('E662',#1185,#1216,#1214,.T.);
#1218=ORIENTED_EDGE('',*,*,#1217,.T.);
#1219=DIRECTION('',(0.,0.,-1.));
#1220=VECTOR('',#1219,1.);
#1221=CARTESIAN_POINT('',(228.,195.,4.));
#1222=LINE('',#1221,#1220);
#1223=CARTESIAN_POINT('',(228.,195.,4.));
#1224=VERTEX_POINT('',#1223);
#1225=EDGE_CURVE('E878',#1224,#1216,#1222,.T.);
#1226=ORIENTED_EDGE('',*,*,#1225,.F.);
#1227=DIRECTION('',(0.,-1.,0.));
#1228=VECTOR('',#1227,1.);
#1229=CARTESIAN_POINT('',(228.,0.,4.));
#1230=LINE('',#1229,#1228);
#1231=EDGE_CURVE('E1082',#1193,#1224,#1230,.T.);
#1232=ORIENTED_EDGE('',*,*,#1231,.F.);
#1233=ORIENTED_EDGE('',*,*,#1194,.T.);
#1234=EDGE_LOOP('',(#1218,#1226,#1232,#1233));
#1235=FACE_BOUND('',#1234,.T.);
#1236=ADVANCED_FACE('F1333',(#1235),#1210,.F.);
#1237=CARTESIAN_POINT('',(0.,195.,4.));
#1238=DIRECTION('',(0.,-1.,0.));
#1239=DIRECTION('',(0.,0.,-1.));
#1240=AXIS2_PLACEMENT_3D('',#1237,#1238,#1239);
#1241=PLANE('',#1240);
#1242=DIRECTION('',(-1.,0.,0.));
#1243=VECTOR('',#1242,1.);
#1244=CARTESIAN_POINT('',(0.,195.,0.));
#1245=LINE('',#1244,#1243);
#1246=CARTESIAN_POINT('',(219.67,195.,0.));
#1247=VERTEX_POINT('',#1246);
#1248=EDGE_CURVE('E664',#1216,#1247,#1245,.T.);
#1249=ORIENTED_EDGE('',*,*,#1248,.T.);
#1250=DIRECTION('',(0.,0.,-1.));
#1251=VECTOR('',#1250,1.);
#1252=CARTESIAN_POINT('',(219.67,195.,4.));
#1253=LINE('',#1252,#1251);
#1254=CARTESIAN_POINT('',(219.67,195.,4.));
#1255=VERTEX_POINT('',#1254);
#1256=EDGE_CURVE('E875',#1255,#1247,#1253,.T.);
#1257=ORIENTED_EDGE('',*,*,#1256,.F.);
#1258=DIRECTION('',(-1.,0.,0.));
#1259=VECTOR('',#1258,1.);
#1260=CARTESIAN_POINT('',(0.,195.,4.));
#1261=LINE('',#1260,#1259);
#1262=EDGE_CURVE('E1084',#1224,#1255,#1261,.T.);
#1263=ORIENTED_EDGE('',*,*,#1262,.F.);
#1264=ORIENTED_EDGE('',*,*,#1225,.T.);
#1265=EDGE_LOOP('',(#1249,#1257,#1263,#1264));
#1266=FACE_BOUND('',#1265,.T.);
#1267=ADVANCED_FACE('F1337',(#1266),#1241,.F.);
#1268=CARTESIAN_POINT('',(219.67,0.,4.));
#1269=DIRECTION('',(-1.,0.,0.));
#1270=DIRECTION('',(0.,0.,1.));
#1271=AXIS2_PLACEMENT_3D('',#1268,#1269,#1270);
#1272=PLANE('',#1271);
#1273=DIRECTION('',(0.,1.,0.));
#1274=VECTOR('',#1273,1.);
#1275=CARTESIAN_POINT('',(219.67,0.,0.));
#1276=LINE('',#1275,#1274);
#1277=CARTESIAN_POINT('',(219.67,199.,0.));
#1278=VERTEX_POINT('',#1277);
#1279=EDGE_CURVE('E666',#1247,#1278,#1276,.T.);
#1280=ORIENTED_EDGE('',*,*,#1279,.T.);
#1281=DIRECTION('',(0.,0.,-1.));
#1282=VECTOR('',#1281,1.);
#1283=CARTESIAN_POINT('',(219.67,199.,4.));
#1284=LINE('',#1283,#1282);
#1285=CARTESIAN_POINT('',(219.67,199.,4.));
#1286=VERTEX_POINT('',#1285);
#1287=EDGE_CURVE('E872',#1286,#1278,#1284,.T.);
#1288=ORIENTED_EDGE('',*,*,#1287,.F.);
#1289=DIRECTION('',(0.,1.,0.));
#1290=VECTOR('',#1289,1.);
#1291=CARTESIAN_POINT('',(219.67,0.,4.));
#1292=LINE('',#1291,#1290);
#1293=EDGE_CURVE('E1086',#1255,#1286,#1292,.T.);
#1294=ORIENTED_EDGE('',*,*,#1293,.F.);
#1295=ORIENTED_EDGE('',*,*,#1256,.T.);
#1296=EDGE_LOOP('',(#1280,#1288,#1294,#1295));
#1297=FACE_BOUND('',#1296,.T.);
#1298=ADVANCED_FACE('F1341',(#1297),#1272,.F.);
#1299=CARTESIAN_POINT('',(0.,199.,4.));
#1300=DIRECTION('',(0.,-1.,0.));
#1301=DIRECTION('',(0.,0.,-1.));
#1302=AXIS2_PLACEMENT_3D('',#1299,#1300,#1301);
#1303=PLANE('',#1302);
#1304=DIRECTION('',(-1.,0.,0.));
#1305=VECTOR('',#1304,1.);
#1306=CARTESIAN_POINT('',(0.,199.,0.));
#1307=LINE('',#1306,#1305);
#1308=CARTESIAN_POINT('',(211.33,199.,0.));
#1309=VERTEX_POINT('',#1308);
#1310=EDGE_CURVE('E668',#1278,#1309,#1307,.T.);
#1311=ORIENTED_EDGE('',*,*,#1310,.T.);
#1312=DIRECTION('',(0.,0.,-1.));
#1313=VECTOR('',#1312,1.);
#1314=CARTESIAN_POINT('',(211.33,199.,4.));
#1315=LINE('',#1314,#1313);
#1316=CARTESIAN_POINT('',(211.33,199.,4.));
#1317=VERTEX_POINT('',#1316);
#1318=EDGE_CURVE('E869',#1317,#1309,#1315,.T.);
#1319=ORIENTED_EDGE('',*,*,#1318,.F.);
#1320=DIRECTION('',(-1.,0.,0.));
#1321=VECTOR('',#1320,1.);
#1322=CARTESIAN_POINT('',(0.,199.,4.));
#1323=LINE('',#1322,#1321);
#1324=EDGE_CURVE('E1088',#1286,#1317,#1323,.T.);
#1325=ORIENTED_EDGE('',*,*,#1324,.F.);
#1326=ORIENTED_EDGE('',*,*,#1287,.T.);
#1327=EDGE_LOOP('',(#1311,#1319,#1325,#1326));
#1328=FACE_BOUND('',#1327,.T.);
#1329=ADVANCED_FACE('F1345',(#1328),#1303,.F.);
#1330=CARTESIAN_POINT('',(211.33,0.,4.));
#1331=DIRECTION('',(1.,0.,0.));
#1332=DIRECTION('',(0.,0.,-1.));
#1333=AXIS2_PLACEMENT_3D('',#1330,#1331,#1332);
#1334=PLANE('',#1333);
#1335=DIRECTION('',(0.,-1.,0.));
#1336=VECTOR('',#1335,1.);
#1337=CARTESIAN_POINT('',(211.33,0.,0.));
#1338=LINE('',#1337,#1336);
#1339=CARTESIAN_POINT('',(211.33,195.,0.));
#1340=VERTEX_POINT('',#1339);
#1341=EDGE_CURVE('E670',#1309,#1340,#1338,.T.);
#1342=ORIENTED_EDGE('',*,*,#1341,.T.);
#1343=DIRECTION('',(0.,0.,-1.));
#1344=VECTOR('',#1343,1.);
#1345=CARTESIAN_POINT('',(211.33,195.,4.));
#1346=LINE('',#1345,#1344);
#1347=CARTESIAN_POINT('',(211.33,195.,4.));
#1348=VERTEX_POINT('',#1347);
#1349=EDGE_CURVE('E866',#1348,#1340,#1346,.T.);
#1350=ORIENTED_EDGE('',*,*,#1349,.F.);
#1351=DIRECTION('',(0.,-1.,0.));
#1352=VECTOR('',#1351,1.);
#1353=CARTESIAN_POINT('',(211.33,0.,4.));
#1354=LINE('',#1353,#1352);
#1355=EDGE_CURVE('E1090',#1317,#1348,#1354,.T.);
#1356=ORIENTED_EDGE('',*,*,#1355,.F.);
#1357=ORIENTED_EDGE('',*,*,#1318,.T.);
#1358=EDGE_LOOP('',(#1342,#1350,#1356,#1357));
#1359=FACE_BOUND('',#1358,.T.);
#1360=ADVANCED_FACE('F1349',(#1359),#1334,.F.);
#1361=CARTESIAN_POINT('',(0.,195.,4.));
#1362=DIRECTION('',(0.,-1.,0.));
#1363=DIRECTION('',(0.,0.,-1.));
#1364=AXIS2_PLACEMENT_3D('',#1361,#1362,#1363);
#1365=PLANE('',#1364);
#1366=DIRECTION('',(-1.,0.,0.));
#1367=VECTOR('',#1366,1.);
#1368=CARTESIAN_POINT('',(0.,195.,0.));
#1369=LINE('',#1368,#1367);
#1370=CARTESIAN_POINT('',(203.,195.,0.));
#1371=VERTEX_POINT('',#1370);
#1372=EDGE_CURVE('E672',#1340,#1371,#1369,.T.);
#1373=ORIENTED_EDGE('',*,*,#1372,.T.);
#1374=DIRECTION('',(0.,0.,-1.));
#1375=VECTOR('',#1374,1.);
#1376=CARTESIAN_POINT('',(203.,195.,4.));
#1377=LINE('',#1376,#1375);
#1378=CARTESIAN_POINT('',(203.,195.,4.));
#1379=VERTEX_POINT('',#1378);
#1380=EDGE_CURVE('E863',#1379,#1371,#1377,.T.);
#1381=ORIENTED_EDGE('',*,*,#1380,.F.);
#1382=DIRECTION('',(-1.,0.,0.));
#1383=VECTOR('',#1382,1.);
#1384=CARTESIAN_POINT('',(0.,195.,4.));
#1385=LINE('',#1384,#1383);
#1386=EDGE_CURVE('E1092',#1348,#1379,#1385,.T.);
#1387=ORIENTED_EDGE('',*,*,#1386,.F.);
#1388=ORIENTED_EDGE('',*,*,#1349,.T.);
#1389=EDGE_LOOP('',(#1373,#1381,#1387,#1388));
#1390=FACE_BOUND('',#1389,.T.);
#1391=ADVANCED_FACE('F1353',(#1390),#1365,.F.);
#1392=CARTESIAN_POINT('',(203.,0.,4.));
#1393=DIRECTION('',(1.,0.,0.));
#1394=DIRECTION('',(0.,0.,-1.));
#1395=AXIS2_PLACEMENT_3D('',#1392,#1393,#1394);
#1396=PLANE('',#1395);
#1397=DIRECTION('',(0.,-1.,0.));
#1398=VECTOR('',#1397,1.);
#1399=CARTESIAN_POINT('',(203.,0.,0.));
#1400=LINE('',#1399,#1398);
#1401=CARTESIAN_POINT('',(203.,186.38,0.));
#1402=VERTEX_POINT('',#1401);
#1403=EDGE_CURVE('E674',#1371,#1402,#1400,.T.);
#1404=ORIENTED_EDGE('',*,*,#1403,.T.);
#1405=DIRECTION('',(0.,0.,-1.));
#1406=VECTOR('',#1405,1.);
#1407=CARTESIAN_POINT('',(203.,186.38,4.));
#1408=LINE('',#1407,#1406);
#1409=CARTESIAN_POINT('',(203.,186.38,4.));
#1410=VERTEX_POINT('',#1409);
#1411=EDGE_CURVE('E860',#1410,#1402,#1408,.T.);
#1412=ORIENTED_EDGE('',*,*,#1411,.F.);
#1413=DIRECTION('',(0.,-1.,0.));
#1414=VECTOR('',#1413,1.);
#1415=CARTESIAN_POINT('',(203.,0.,4.));
#1416=LINE('',#1415,#1414);
#1417=EDGE_CURVE('E1094',#1379,#1410,#1416,.T.);
#1418=ORIENTED_EDGE('',*,*,#1417,.F.);
#1419=ORIENTED_EDGE('',*,*,#1380,.T.);
#1420=EDGE_LOOP('',(#1404,#1412,#1418,#1419));
#1421=FACE_BOUND('',#1420,.T.);
#1422=ADVANCED_FACE('F1357',(#1421),#1396,.F.);
#1423=CARTESIAN_POINT('',(0.,186.38,4.));
#1424=DIRECTION('',(0.,1.,0.));
#1425=DIRECTION('',(0.,0.,1.));
#1426=AXIS2_PLACEMENT_3D('',#1423,#1424,#1425);
#1427=PLANE('',#1426);
#1428=DIRECTION('',(1.,0.,0.));
#1429=VECTOR('',#1428,1.);
#1430=CARTESIAN_POINT('',(0.,186.38,0.));
#1431=LINE('',#1430,#1429);
#1432=CARTESIAN_POINT('',(207.,186.38,0.));
#1433=VERTEX_POINT('',#1432);
#1434=EDGE_CURVE('E676',#1402,#1433,#1431,.T.);
#1435=ORIENTED_EDGE('',*,*,#1434,.T.);
#1436=DIRECTION('',(0.,0.,-1.));
#1437=VECTOR('',#1436,1.);
#1438=CARTESIAN_POINT('',(207.,186.38,4.));
#1439=LINE('',#1438,#1437);
#1440=CARTESIAN_POINT('',(207.,186.38,4.));
#1441=VERTEX_POINT('',#1440);
#1442=EDGE_CURVE('E857',#1441,#1433,#1439,.T.);
#1443=ORIENTED_EDGE('',*,*,#1442,.F.);
#1444=DIRECTION('',(1.,0.,0.));
#1445=VECTOR('',#1444,1.);
#1446=CARTESIAN_POINT('',(0.,186.38,4.));
#1447=LINE('',#1446,#1445);
#1448=EDGE_CURVE('E1096',#1410,#1441,#1447,.T.);
#1449=ORIENTED_EDGE('',*,*,#1448,.F.);
#1450=ORIENTED_EDGE('',*,*,#1411,.T.);
#1451=EDGE_LOOP('',(#1435,#1443,#1449,#1450));
#1452=FACE_BOUND('',#1451,.T.);
#1453=ADVANCED_FACE('F1361',(#1452),#1427,.F.);
#1454=CARTESIAN_POINT('',(207.,0.,4.));
#1455=DIRECTION('',(1.,0.,0.));
#1456=DIRECTION('',(0.,0.,-1.));
#1457=AXIS2_PLACEMENT_3D('',#1454,#1455,#1456);
#1458=PLANE('',#1457);
#1459=DIRECTION('',(0.,-1.,0.));
#1460=VECTOR('',#1459,1.);
#1461=CARTESIAN_POINT('',(207.,0.,0.));
#1462=LINE('',#1461,#1460);
#1463=CARTESIAN_POINT('',(207.,177.77,0.));
#1464=VERTEX_POINT('',#1463);
#1465=EDGE_CURVE('E678',#1433,#1464,#1462,.T.);
#1466=ORIENTED_EDGE('',*,*,#1465,.T.);
#1467=DIRECTION('',(0.,0.,-1.));
#1468=VECTOR('',#1467,1.);
#1469=CARTESIAN_POINT('',(207.,177.77,4.));
#1470=LINE('',#1469,#1468);
#1471=CARTESIAN_POINT('',(207.,177.77,4.));
#1472=VERTEX_POINT('',#1471);
#1473=EDGE_CURVE('E854',#1472,#1464,#1470,.T.);
#1474=ORIENTED_EDGE('',*,*,#1473,.F.);
#1475=DIRECTION('',(0.,-1.,0.));
#1476=VECTOR('',#1475,1.);
#1477=CARTESIAN_POINT('',(207.,0.,4.));
#1478=LINE('',#1477,#1476);
#1479=EDGE_CURVE('E1098',#1441,#1472,#1478,.T.);
#1480=ORIENTED_EDGE('',*,*,#1479,.F.);
#1481=ORIENTED_EDGE('',*,*,#1442,.T.);
#1482=EDGE_LOOP('',(#1466,#1474,#1480,#1481));
#1483=FACE_BOUND('',#1482,.T.);
#1484=ADVANCED_FACE('F1365',(#1483),#1458,.F.);
#1485=CARTESIAN_POINT('',(0.,177.77,4.));
#1486=DIRECTION('',(0.,-1.,0.));
#1487=DIRECTION('',(0.,0.,-1.));
#1488=AXIS2_PLACEMENT_3D('',#1485,#1486,#1487);
#1489=PLANE('',#1488);
#1490=DIRECTION('',(-1.,0.,0.));
#1491=VECTOR('',#1490,1.);
#1492=CARTESIAN_POINT('',(0.,177.77,0.));
#1493=LINE('',#1492,#1491);
#1494=CARTESIAN_POINT('',(203.,177.77,0.));
#1495=VERTEX_POINT('',#1494);
#1496=EDGE_CURVE('E680',#1464,#1495,#1493,.T.);
#1497=ORIENTED_EDGE('',*,*,#1496,.T.);
#1498=DIRECTION('',(0.,0.,-1.));
#1499=VECTOR('',#1498,1.);
#1500=CARTESIAN_POINT('',(203.,177.77,4.));
#1501=LINE('',#1500,#1499);
#1502=CARTESIAN_POINT('',(203.,177.77,4.));
#1503=VERTEX_POINT('',#1502);
#1504=EDGE_CURVE('E851',#1503,#1495,#1501,.T.);
#1505=ORIENTED_EDGE('',*,*,#1504,.F.);
#1506=DIRECTION('',(-1.,0.,0.));
#1507=VECTOR('',#1506,1.);
#1508=CARTESIAN_POINT('',(0.,177.77,4.));
#1509=LINE('',#1508,#1507);
#1510=EDGE_CURVE('E1100',#1472,#1503,#1509,.T.);
#1511=ORIENTED_EDGE('',*,*,#1510,.F.);
#1512=ORIENTED_EDGE('',*,*,#1473,.T.);
#1513=EDGE_LOOP('',(#1497,#1505,#1511,#1512));
#1514=FACE_BOUND('',#1513,.T.);
#1515=ADVANCED_FACE('F1369',(#1514),#1489,.F.);
#1516=CARTESIAN_POINT('',(203.,0.,4.));
#1517=DIRECTION('',(1.,0.,0.));
#1518=DIRECTION('',(0.,0.,-1.));
#1519=AXIS2_PLACEMENT_3D('',#1516,#1517,#1518);
#1520=PLANE('',#1519);
#1521=DIRECTION('',(0.,-1.,0.));
#1522=VECTOR('',#1521,1.);
#1523=CARTESIAN_POINT('',(203.,0.,0.));
#1524=LINE('',#1523,#1522);
#1525=CARTESIAN_POINT('',(203.,169.15,0.));
#1526=VERTEX_POINT('',#1525);
#1527=EDGE_CURVE('E682',#1495,#1526,#1524,.T.);
#1528=ORIENTED_EDGE('',*,*,#1527,.T.);
#1529=DIRECTION('',(0.,0.,-1.));
#1530=VECTOR('',#1529,1.);
#1531=CARTESIAN_POINT('',(203.,169.15,4.));
#1532=LINE('',#1531,#1530);
#1533=CARTESIAN_POINT('',(203.,169.15,4.));
#1534=VERTEX_POINT('',#1533);
#1535=EDGE_CURVE('E848',#1534,#1526,#1532,.T.);
#1536=ORIENTED_EDGE('',*,*,#1535,.F.);
#1537=DIRECTION('',(0.,-1.,0.));
#1538=VECTOR('',#1537,1.);
#1539=CARTESIAN_POINT('',(203.,0.,4.));
#1540=LINE('',#1539,#1538);
#1541=EDGE_CURVE('E1102',#1503,#1534,#1540,.T.);
#1542=ORIENTED_EDGE('',*,*,#1541,.F.);
#1543=ORIENTED_EDGE('',*,*,#1504,.T.);
#1544=EDGE_LOOP('',(#1528,#1536,#1542,#1543));
#1545=FACE_BOUND('',#1544,.T.);
#1546=ADVANCED_FACE('F1373',(#1545),#1520,.F.);
#1547=CARTESIAN_POINT('',(0.,169.15,4.));
#1548=DIRECTION('',(0.,1.,0.));
#1549=DIRECTION('',(0.,0.,1.));
#1550=AXIS2_PLACEMENT_3D('',#1547,#1548,#1549);
#1551=PLANE('',#1550);
#1552=DIRECTION('',(1.,0.,0.));
#1553=VECTOR('',#1552,1.);
#1554=CARTESIAN_POINT('',(0.,169.15,0.));
#1555=LINE('',#1554,#1553);
#1556=CARTESIAN_POINT('',(207.,169.15,0.));
#1557=VERTEX_POINT('',#1556);
#1558=EDGE_CURVE('E684',#1526,#1557,#1555,.T.);
#1559=ORIENTED_EDGE('',*,*,#1558,.T.);
#1560=DIRECTION('',(0.,0.,-1.));
#1561=VECTOR('',#1560,1.);
#1562=CARTESIAN_POINT('',(207.,169.15,4.));
#1563=LINE('',#1562,#1561);
#1564=CARTESIAN_POINT('',(207.,169.15,4.));
#1565=VERTEX_POINT('',#1564);
#1566=EDGE_CURVE('E845',#1565,#1557,#1563,.T.);
#1567=ORIENTED_EDGE('',*,*,#1566,.F.);
#1568=DIRECTION('',(1.,0.,0.));
#1569=VECTOR('',#1568,1.);
#1570=CARTESIAN_POINT('',(0.,169.15,4.));
#1571=LINE('',#1570,#1569);
#1572=EDGE_CURVE('E1104',#1534,#1565,#1571,.T.);
#1573=ORIENTED_EDGE('',*,*,#1572,.F.);
#1574=ORIENTED_EDGE('',*,*,#1535,.T.);
#1575=EDGE_LOOP('',(#1559,#1567,#1573,#1574));
#1576=FACE_BOUND('',#1575,.T.);
#1577=ADVANCED_FACE('F1377',(#1576),#1551,.F.);
#1578=CARTESIAN_POINT('',(207.,0.,4.));
#1579=DIRECTION('',(1.,0.,0.));
#1580=DIRECTION('',(0.,0.,-1.));
#1581=AXIS2_PLACEMENT_3D('',#1578,#1579,#1580);
#1582=PLANE('',#1581);
#1583=DIRECTION('',(0.,-1.,0.));
#1584=VECTOR('',#1583,1.);
#1585=CARTESIAN_POINT('',(207.,0.,0.));
#1586=LINE('',#1585,#1584);
#1587=CARTESIAN_POINT('',(207.,160.54,0.));
#1588=VERTEX_POINT('',#1587);
#1589=EDGE_CURVE('E686',#1557,#1588,#1586,.T.);
#1590=ORIENTED_EDGE('',*,*,#1589,.T.);
#1591=DIRECTION('',(0.,0.,-1.));
#1592=VECTOR('',#1591,1.);
#1593=CARTESIAN_POINT('',(207.,160.54,4.));
#1594=LINE('',#1593,#1592);
#1595=CARTESIAN_POINT('',(207.,160.54,4.));
#1596=VERTEX_POINT('',#1595);
#1597=EDGE_CURVE('E842',#1596,#1588,#1594,.T.);
#1598=ORIENTED_EDGE('',*,*,#1597,.F.);
#1599=DIRECTION('',(0.,-1.,0.));
#1600=VECTOR('',#1599,1.);
#1601=CARTESIAN_POINT('',(207.,0.,4.));
#1602=LINE('',#1601,#1600);
#1603=EDGE_CURVE('E1106',#1565,#1596,#1602,.T.);
#1604=ORIENTED_EDGE('',*,*,#1603,.F.);
#1605=ORIENTED_EDGE('',*,*,#1566,.T.);
#1606=EDGE_LOOP('',(#1590,#1598,#1604,#1605));
#1607=FACE_BOUND('',#1606,.T.);
#1608=ADVANCED_FACE('F1381',(#1607),#1582,.F.);
#1609=CARTESIAN_POINT('',(0.,160.54,4.));
#1610=DIRECTION('',(0.,-1.,0.));
#1611=DIRECTION('',(0.,0.,-1.));
#1612=AXIS2_PLACEMENT_3D('',#1609,#1610,#1611);
#1613=PLANE('',#1612);
#1614=DIRECTION('',(-1.,0.,0.));
#1615=VECTOR('',#1614,1.);
#1616=CARTESIAN_POINT('',(0.,160.54,0.));
#1617=LINE('',#1616,#1615);
#1618=CARTESIAN_POINT('',(203.,160.54,0.));
#1619=VERTEX_POINT('',#1618);
#1620=EDGE_CURVE('E688',#1588,#1619,#1617,.T.);
#1621=ORIENTED_EDGE('',*,*,#1620,.T.);
#1622=DIRECTION('',(0.,0.,-1.));
#1623=VECTOR('',#1622,1.);
#1624=CARTESIAN_POINT('',(203.,160.54,4.));
#1625=LINE('',#1624,#1623);
#1626=CARTESIAN_POINT('',(203.,160.54,4.));
#1627=VERTEX_POINT('',#1626);
#1628=EDGE_CURVE('E839',#1627,#1619,#1625,.T.);
#1629=ORIENTED_EDGE('',*,*,#1628,.F.);
#1630=DIRECTION('',(-1.,0.,0.));
#1631=VECTOR('',#1630,1.);
#1632=CARTESIAN_POINT('',(0.,160.54,4.));
#1633=LINE('',#1632,#1631);
#1634=EDGE_CURVE('E1108',#1596,#1627,#1633,.T.);
#1635=ORIENTED_EDGE('',*,*,#1634,.F.);
#1636=ORIENTED_EDGE('',*,*,#1597,.T.);
#1637=EDGE_LOOP('',(#1621,#1629,#1635,#1636));
#1638=FACE_BOUND('',#1637,.T.);
#1639=ADVANCED_FACE('F1385',(#1638),#1613,.F.);
#1640=CARTESIAN_POINT('',(203.,0.,4.));
#1641=DIRECTION('',(1.,0.,0.));
#1642=DIRECTION('',(0.,0.,-1.));
#1643=AXIS2_PLACEMENT_3D('',#1640,#1641,#1642);
#1644=PLANE('',#1643);
#1645=DIRECTION('',(0.,-1.,0.));
#1646=VECTOR('',#1645,1.);
#1647=CARTESIAN_POINT('',(203.,0.,0.));
#1648=LINE('',#1647,#1646);
#1649=CARTESIAN_POINT('',(203.,151.92,0.));
#1650=VERTEX_POINT('',#1649);
#1651=EDGE_CURVE('E690',#1619,#1650,#1648,.T.);
#1652=ORIENTED_EDGE('',*,*,#1651,.T.);
#1653=DIRECTION('',(0.,0.,-1.));
#1654=VECTOR('',#1653,1.);
#1655=CARTESIAN_POINT('',(203.,151.92,4.));
#1656=LINE('',#1655,#1654);
#1657=CARTESIAN_POINT('',(203.,151.92,4.));
#1658=VERTEX_POINT('',#1657);
#1659=EDGE_CURVE('E836',#1658,#1650,#1656,.T.);
#1660=ORIENTED_EDGE('',*,*,#1659,.F.);
#1661=DIRECTION('',(0.,-1.,0.));
#1662=VECTOR('',#1661,1.);
#1663=CARTESIAN_POINT('',(203.,0.,4.));
#1664=LINE('',#1663,#1662);
#1665=EDGE_CURVE('E1110',#1627,#1658,#1664,.T.);
#1666=ORIENTED_EDGE('',*,*,#1665,.F.);
#1667=ORIENTED_EDGE('',*,*,#1628,.T.);
#1668=EDGE_LOOP('',(#1652,#1660,#1666,#1667));
#1669=FACE_BOUND('',#1668,.T.);
#1670=ADVANCED_FACE('F1389',(#1669),#1644,.F.);
#1671=CARTESIAN_POINT('',(0.,151.92,4.));
#1672=DIRECTION('',(0.,1.,0.));
#1673=DIRECTION('',(0.,0.,1.));
#1674=AXIS2_PLACEMENT_3D('',#1671,#1672,#1673);
#1675=PLANE('',#1674);
#1676=DIRECTION('',(1.,0.,0.));
#1677=VECTOR('',#1676,1.);
#1678=CARTESIAN_POINT('',(0.,151.92,0.));
#1679=LINE('',#1678,#1677);
#1680=CARTESIAN_POINT('',(207.,151.92,0.));
#1681=VERTEX_POINT('',#1680);
#1682=EDGE_CURVE('E692',#1650,#1681,#1679,.T.);
#1683=ORIENTED_EDGE('',*,*,#1682,.T.);
#1684=DIRECTION('',(0.,0.,-1.));
#1685=VECTOR('',#1684,1.);
#1686=CARTESIAN_POINT('',(207.,151.92,4.));
#1687=LINE('',#1686,#1685);
#1688=CARTESIAN_POINT('',(207.,151.92,4.));
#1689=VERTEX_POINT('',#1688);
#1690=EDGE_CURVE('E833',#1689,#1681,#1687,.T.);
#1691=ORIENTED_EDGE('',*,*,#1690,.F.);
#1692=DIRECTION('',(1.,0.,0.));
#1693=VECTOR('',#1692,1.);
#1694=CARTESIAN_POINT('',(0.,151.92,4.));
#1695=LINE('',#1694,#1693);
#1696=EDGE_CURVE('E1112',#1658,#1689,#1695,.T.);
#1697=ORIENTED_EDGE('',*,*,#1696,.F.);
#1698=ORIENTED_EDGE('',*,*,#1659,.T.);
#1699=EDGE_LOOP('',(#1683,#1691,#1697,#1698));
#1700=FACE_BOUND('',#1699,.T.);
#1701=ADVANCED_FACE('F1393',(#1700),#1675,.F.);
#1702=CARTESIAN_POINT('',(207.,0.,4.));
#1703=DIRECTION('',(1.,0.,0.));
#1704=DIRECTION('',(0.,0.,-1.));
#1705=AXIS2_PLACEMENT_3D('',#1702,#1703,#1704);
#1706=PLANE('',#1705);
#1707=DIRECTION('',(0.,-1.,0.));
#1708=VECTOR('',#1707,1.);
#1709=CARTESIAN_POINT('',(207.,0.,0.));
#1710=LINE('',#1709,#1708);
#1711=CARTESIAN_POINT('',(207.,143.31,0.));
#1712=VERTEX_POINT('',#1711);
#1713=EDGE_CURVE('E694',#1681,#1712,#1710,.T.);
#1714=ORIENTED_EDGE('',*,*,#1713,.T.);
#1715=DIRECTION('',(0.,0.,-1.));
#1716=VECTOR('',#1715,1.);
#1717=CARTESIAN_POINT('',(207.,143.31,4.));
#1718=LINE('',#1717,#1716);
#1719=CARTESIAN_POINT('',(207.,143.31,4.));
#1720=VERTEX_POINT('',#1719);
#1721=EDGE_CURVE('E830',#1720,#1712,#1718,.T.);
#1722=ORIENTED_EDGE('',*,*,#1721,.F.);
#1723=DIRECTION('',(0.,-1.,0.));
#1724=VECTOR('',#1723,1.);
#1725=CARTESIAN_POINT('',(207.,0.,4.));
#1726=LINE('',#1725,#1724);
#1727=EDGE_CURVE('E1114',#1689,#1720,#1726,.T.);
#1728=ORIENTED_EDGE('',*,*,#1727,.F.);
#1729=ORIENTED_EDGE('',*,*,#1690,.T.);
#1730=EDGE_LOOP('',(#1714,#1722,#1728,#1729));
#1731=FACE_BOUND('',#1730,.T.);
#1732=ADVANCED_FACE('F1397',(#1731),#1706,.F.);
#1733=CARTESIAN_POINT('',(0.,143.31,4.));
#1734=DIRECTION('',(0.,-1.,0.));
#1735=DIRECTION('',(0.,0.,-1.));
#1736=AXIS2_PLACEMENT_3D('',#1733,#1734,#1735);
#1737=PLANE('',#1736);
#1738=DIRECTION('',(-1.,0.,0.));
#1739=VECTOR('',#1738,1.);
#1740=CARTESIAN_POINT('',(0.,143.31,0.));
#1741=LINE('',#1740,#1739);
#1742=CARTESIAN_POINT('',(203.,143.31,0.));
#1743=VERTEX_POINT('',#1742);
#1744=EDGE_CURVE('E696',#1712,#1743,#1741,.T.);
#1745=ORIENTED_EDGE('',*,*,#1744,.T.);
#1746=DIRECTION('',(0.,0.,-1.));
#1747=VECTOR('',#1746,1.);
#1748=CARTESIAN_POINT('',(203.,143.31,4.));
#1749=LINE('',#1748,#1747);
#1750=CARTESIAN_POINT('',(203.,143.31,4.));
#1751=VERTEX_POINT('',#1750);
#1752=EDGE_CURVE('E827',#1751,#1743,#1749,.T.);
#1753=ORIENTED_EDGE('',*,*,#1752,.F.);
#1754=DIRECTION('',(-1.,0.,0.));
#1755=VECTOR('',#1754,1.);
#1756=CARTESIAN_POINT('',(0.,143.31,4.));
#1757=LINE('',#1756,#1755);
#1758=EDGE_CURVE('E1116',#1720,#1751,#1757,.T.);
#1759=ORIENTED_EDGE('',*,*,#1758,.F.);
#1760=ORIENTED_EDGE('',*,*,#1721,.T.);
#1761=EDGE_LOOP('',(#1745,#1753,#1759,#1760));
#1762=FACE_BOUND('',#1761,.T.);
#1763=ADVANCED_FACE('F1401',(#1762),#1737,.F.);
#1764=CARTESIAN_POINT('',(203.,0.,4.));
#1765=DIRECTION('',(1.,0.,0.));
#1766=DIRECTION('',(0.,0.,-1.));
#1767=AXIS2_PLACEMENT_3D('',#1764,#1765,#1766);
#1768=PLANE('',#1767);
#1769=DIRECTION('',(0.,-1.,0.));
#1770=VECTOR('',#1769,1.);
#1771=CARTESIAN_POINT('',(203.,0.,0.));
#1772=LINE('',#1771,#1770);
#1773=CARTESIAN_POINT('',(203.,134.69,0.));
#1774=VERTEX_POINT('',#1773);
#1775=EDGE_CURVE('E698',#1743,#1774,#1772,.T.);
#1776=ORIENTED_EDGE('',*,*,#1775,.T.);
#1777=DIRECTION('',(0.,0.,-1.));
#1778=VECTOR('',#1777,1.);
#1779=CARTESIAN_POINT('',(203.,134.69,4.));
#1780=LINE('',#1779,#1778);
#1781=CARTESIAN_POINT('',(203.,134.69,4.));
#1782=VERTEX_POINT('',#1781);
#1783=EDGE_CURVE('E824',#1782,#1774,#1780,.T.);
#1784=ORIENTED_EDGE('',*,*,#1783,.F.);
#1785=DIRECTION('',(0.,-1.,0.));
#1786=VECTOR('',#1785,1.);
#1787=CARTESIAN_POINT('',(203.,0.,4.));
#1788=LINE('',#1787,#1786);
#1789=EDGE_CURVE('E1118',#1751,#1782,#1788,.T.);
#1790=ORIENTED_EDGE('',*,*,#1789,.F.);
#1791=ORIENTED_EDGE('',*,*,#1752,.T.);
#1792=EDGE_LOOP('',(#1776,#1784,#1790,#1791));
#1793=FACE_BOUND('',#1792,.T.);
#1794=ADVANCED_FACE('F1405',(#1793),#1768,.F.);
#1795=CARTESIAN_POINT('',(0.,134.69,4.));
#1796=DIRECTION('',(0.,1.,0.));
#1797=DIRECTION('',(0.,0.,1.));
#1798=AXIS2_PLACEMENT_3D('',#1795,#1796,#1797);
#1799=PLANE('',#1798);
#1800=DIRECTION('',(1.,0.,0.));
#1801=VECTOR('',#1800,1.);
#1802=CARTESIAN_POINT('',(0.,134.69,0.));
#1803=LINE('',#1802,#1801);
#1804=CARTESIAN_POINT('',(207.,134.69,0.));
#1805=VERTEX_POINT('',#1804);
#1806=EDGE_CURVE('E700',#1774,#1805,#1803,.T.);
#1807=ORIENTED_EDGE('',*,*,#1806,.T.);
#1808=DIRECTION('',(0.,0.,-1.));
#1809=VECTOR('',#1808,1.);
#1810=CARTESIAN_POINT('',(207.,134.69,4.));
#1811=LINE('',#1810,#1809);
#1812=CARTESIAN_POINT('',(207.,134.69,4.));
#1813=VERTEX_POINT('',#1812);
#1814=EDGE_CURVE('E821',#1813,#1805,#1811,.T.);
#1815=ORIENTED_EDGE('',*,*,#1814,.F.);
#1816=DIRECTION('',(1.,0.,0.));
#1817=VECTOR('',#1816,1.);
#1818=CARTESIAN_POINT('',(0.,134.69,4.));
#1819=LINE('',#1818,#1817);
#1820=EDGE_CURVE('E1120',#1782,#1813,#1819,.T.);
#1821=ORIENTED_EDGE('',*,*,#1820,.F.);
#1822=ORIENTED_EDGE('',*,*,#1783,.T.);
#1823=EDGE_LOOP('',(#1807,#1815,#1821,#1822));
#1824=FACE_BOUND('',#1823,.T.);
#1825=ADVANCED_FACE('F1409',(#1824),#1799,.F.);
#1826=CARTESIAN_POINT('',(207.,0.,4.));
#1827=DIRECTION('',(1.,0.,0.));
#1828=DIRECTION('',(0.,0.,-1.));
#1829=AXIS2_PLACEMENT_3D('',#1826,#1827,#1828);
#1830=PLANE('',#1829);
#1831=DIRECTION('',(0.,-1.,0.));
#1832=VECTOR('',#1831,1.);
#1833=CARTESIAN_POINT('',(207.,0.,0.));
#1834=LINE('',#1833,#1832);
#1835=CARTESIAN_POINT('',(207.,126.08,0.));
#1836=VERTEX_POINT('',#1835);
#1837=EDGE_CURVE('E702',#1805,#1836,#1834,.T.);
#1838=ORIENTED_EDGE('',*,*,#1837,.T.);
#1839=DIRECTION('',(0.,0.,-1.));
#1840=VECTOR('',#1839,1.);
#1841=CARTESIAN_POINT('',(207.,126.08,4.));
#1842=LINE('',#1841,#1840);
#1843=CARTESIAN_POINT('',(207.,126.08,4.));
#1844=VERTEX_POINT('',#1843);
#1845=EDGE_CURVE('E818',#1844,#1836,#1842,.T.);
#1846=ORIENTED_EDGE('',*,*,#1845,.F.);
#1847=DIRECTION('',(0.,-1.,0.));
#1848=VECTOR('',#1847,1.);
#1849=CARTESIAN_POINT('',(207.,0.,4.));
#1850=LINE('',#1849,#1848);
#1851=EDGE_CURVE('E1122',#1813,#1844,#1850,.T.);
#1852=ORIENTED_EDGE('',*,*,#1851,.F.);
#1853=ORIENTED_EDGE('',*,*,#1814,.T.);
#1854=EDGE_LOOP('',(#1838,#1846,#1852,#1853));
#1855=FACE_BOUND('',#1854,.T.);
#1856=ADVANCED_FACE('F1413',(#1855),#1830,.F.);
#1857=CARTESIAN_POINT('',(0.,126.08,4.));
#1858=DIRECTION('',(0.,-1.,0.));
#1859=DIRECTION('',(0.,0.,-1.));
#1860=AXIS2_PLACEMENT_3D('',#1857,#1858,#1859);
#1861=PLANE('',#1860);
#1862=DIRECTION('',(-1.,0.,0.));
#1863=VECTOR('',#1862,1.);
#1864=CARTESIAN_POINT('',(0.,126.08,0.));
#1865=LINE('',#1864,#1863);
#1866=CARTESIAN_POINT('',(203.,126.08,0.));
#1867=VERTEX_POINT('',#1866);
#1868=EDGE_CURVE('E704',#1836,#1867,#1865,.T.);
#1869=ORIENTED_EDGE('',*,*,#1868,.T.);
#1870=DIRECTION('',(0.,0.,-1.));
#1871=VECTOR('',#1870,1.);
#1872=CARTESIAN_POINT('',(203.,126.08,4.));
#1873=LINE('',#1872,#1871);
#1874=CARTESIAN_POINT('',(203.,126.08,4.));
#1875=VERTEX_POINT('',#1874);
#1876=EDGE_CURVE('E815',#1875,#1867,#1873,.T.);
#1877=ORIENTED_EDGE('',*,*,#1876,.F.);
#1878=DIRECTION('',(-1.,0.,0.));
#1879=VECTOR('',#1878,1.);
#1880=CARTESIAN_POINT('',(0.,126.08,4.));
#1881=LINE('',#1880,#1879);
#1882=EDGE_CURVE('E1124',#1844,#1875,#1881,.T.);
#1883=ORIENTED_EDGE('',*,*,#1882,.F.);
#1884=ORIENTED_EDGE('',*,*,#1845,.T.);
#1885=EDGE_LOOP('',(#1869,#1877,#1883,#1884));
#1886=FACE_BOUND('',#1885,.T.);
#1887=ADVANCED_FACE('F1417',(#1886),#1861,.F.);
#1888=CARTESIAN_POINT('',(203.,0.,4.));
#1889=DIRECTION('',(1.,0.,0.));
#1890=DIRECTION('',(0.,0.,-1.));
#1891=AXIS2_PLACEMENT_3D('',#1888,#1889,#1890);
#1892=PLANE('',#1891);
#1893=DIRECTION('',(0.,-1.,0.));
#1894=VECTOR('',#1893,1.);
#1895=CARTESIAN_POINT('',(203.,0.,0.));
#1896=LINE('',#1895,#1894);
#1897=CARTESIAN_POINT('',(203.,117.46,0.));
#1898=VERTEX_POINT('',#1897);
#1899=EDGE_CURVE('E706',#1867,#1898,#1896,.T.);
#1900=ORIENTED_EDGE('',*,*,#1899,.T.);
#1901=DIRECTION('',(0.,0.,-1.));
#1902=VECTOR('',#1901,1.);
#1903=CARTESIAN_POINT('',(203.,117.46,4.));
#1904=LINE('',#1903,#1902);
#1905=CARTESIAN_POINT('',(203.,117.46,4.));
#1906=VERTEX_POINT('',#1905);
#1907=EDGE_CURVE('E812',#1906,#1898,#1904,.T.);
#1908=ORIENTED_EDGE('',*,*,#1907,.F.);
#1909=DIRECTION('',(0.,-1.,0.));
#1910=VECTOR('',#1909,1.);
#1911=CARTESIAN_POINT('',(203.,0.,4.));
#1912=LINE('',#1911,#1910);
#1913=EDGE_CURVE('E1126',#1875,#1906,#1912,.T.);
#1914=ORIENTED_EDGE('',*,*,#1913,.F.);
#1915=ORIENTED_EDGE('',*,*,#1876,.T.);
#1916=EDGE_LOOP('',(#1900,#1908,#1914,#1915));
#1917=FACE_BOUND('',#1916,.T.);
#1918=ADVANCED_FACE('F1421',(#1917),#1892,.F.);
#1919=CARTESIAN_POINT('',(0.,117.46,4.));
#1920=DIRECTION('',(0.,1.,0.));
#1921=DIRECTION('',(0.,0.,1.));
#1922=AXIS2_PLACEMENT_3D('',#1919,#1920,#1921);
#1923=PLANE('',#1922);
#1924=DIRECTION('',(1.,0.,0.));
#1925=VECTOR('',#1924,1.);
#1926=CARTESIAN_POINT('',(0.,117.46,0.));
#1927=LINE('',#1926,#1925);
#1928=CARTESIAN_POINT('',(207.,117.46,0.));
#1929=VERTEX_POINT('',#1928);
#1930=EDGE_CURVE('E708',#1898,#1929,#1927,.T.);
#1931=ORIENTED_EDGE('',*,*,#1930,.T.);
#1932=DIRECTION('',(0.,0.,-1.));
#1933=VECTOR('',#1932,1.);
#1934=CARTESIAN_POINT('',(207.,117.46,4.));
#1935=LINE('',#1934,#1933);
#1936=CARTESIAN_POINT('',(207.,117.46,4.));
#1937=VERTEX_POINT('',#1936);
#1938=EDGE_CURVE('E809',#1937,#1929,#1935,.T.);
#1939=ORIENTED_EDGE('',*,*,#1938,.F.);
#1940=DIRECTION('',(1.,0.,0.));
#1941=VECTOR('',#1940,1.);
#1942=CARTESIAN_POINT('',(0.,117.46,4.));
#1943=LINE('',#1942,#1941);
#1944=EDGE_CURVE('E1128',#1906,#1937,#1943,.T.);
#1945=ORIENTED_EDGE('',*,*,#1944,.F.);
#1946=ORIENTED_EDGE('',*,*,#1907,.T.);
#1947=EDGE_LOOP('',(#1931,#1939,#1945,#1946));
#1948=FACE_BOUND('',#1947,.T.);
#1949=ADVANCED_FACE('F1425',(#1948),#1923,.F.);
#1950=CARTESIAN_POINT('',(207.,0.,4.));
#1951=DIRECTION('',(1.,0.,0.));
#1952=DIRECTION('',(0.,0.,-1.));
#1953=AXIS2_PLACEMENT_3D('',#1950,#1951,#1952);
#1954=PLANE('',#1953);
#1955=DIRECTION('',(0.,-1.,0.));
#1956=VECTOR('',#1955,1.);
#1957=CARTESIAN_POINT('',(207.,0.,0.));
#1958=LINE('',#1957,#1956);
#1959=CARTESIAN_POINT('',(207.,108.85,0.));
#1960=VERTEX_POINT('',#1959);
#1961=EDGE_CURVE('E710',#1929,#1960,#1958,.T.);
#1962=ORIENTED_EDGE('',*,*,#1961,.T.);
#1963=DIRECTION('',(0.,0.,-1.));
#1964=VECTOR('',#1963,1.);
#1965=CARTESIAN_POINT('',(207.,108.85,4.));
#1966=LINE('',#1965,#1964);
#1967=CARTESIAN_POINT('',(207.,108.85,4.));
#1968=VERTEX_POINT('',#1967);
#1969=EDGE_CURVE('E806',#1968,#1960,#1966,.T.);
#1970=ORIENTED_EDGE('',*,*,#1969,.F.);
#1971=DIRECTION('',(0.,-1.,0.));
#1972=VECTOR('',#1971,1.);
#1973=CARTESIAN_POINT('',(207.,0.,4.));
#1974=LINE('',#1973,#1972);
#1975=EDGE_CURVE('E1130',#1937,#1968,#1974,.T.);
#1976=ORIENTED_EDGE('',*,*,#1975,.F.);
#1977=ORIENTED_EDGE('',*,*,#1938,.T.);
#1978=EDGE_LOOP('',(#1962,#1970,#1976,#1977));
#1979=FACE_BOUND('',#1978,.T.);
#1980=ADVANCED_FACE('F1429',(#1979),#1954,.F.);
#1981=CARTESIAN_POINT('',(0.,108.85,4.));
#1982=DIRECTION('',(0.,-1.,0.));
#1983=DIRECTION('',(0.,0.,-1.));
#1984=AXIS2_PLACEMENT_3D('',#1981,#1982,#1983);
#1985=PLANE('',#1984);
#1986=DIRECTION('',(-1.,0.,0.));
#1987=VECTOR('',#1986,1.);
#1988=CARTESIAN_POINT('',(0.,108.85,0.));
#1989=LINE('',#1988,#1987);
#1990=CARTESIAN_POINT('',(203.,108.85,0.));
#1991=VERTEX_POINT('',#1990);
#1992=EDGE_CURVE('E712',#1960,#1991,#1989,.T.);
#1993=ORIENTED_EDGE('',*,*,#1992,.T.);
#1994=DIRECTION('',(0.,0.,-1.));
#1995=VECTOR('',#1994,1.);
#1996=CARTESIAN_POINT('',(203.,108.85,4.));
#1997=LINE('',#1996,#1995);
#1998=CARTESIAN_POINT('',(203.,108.85,4.));
#1999=VERTEX_POINT('',#1998);
#2000=EDGE_CURVE('E803',#1999,#1991,#1997,.T.);
#2001=ORIENTED_EDGE('',*,*,#2000,.F.);
#2002=DIRECTION('',(-1.,0.,0.));
#2003=VECTOR('',#2002,1.);
#2004=CARTESIAN_POINT('',(0.,108.85,4.));
#2005=LINE('',#2004,#2003);
#2006=EDGE_CURVE('E1132',#1968,#1999,#2005,.T.);
#2007=ORIENTED_EDGE('',*,*,#2006,.F.);
#2008=ORIENTED_EDGE('',*,*,#1969,.T.);
#2009=EDGE_LOOP('',(#1993,#2001,#2007,#2008));
#2010=FACE_BOUND('',#2009,.T.);
#2011=ADVANCED_FACE('F1433',(#2010),#1985,.F.);
#2012=CARTESIAN_POINT('',(203.,0.,4.));
#2013=DIRECTION('',(1.,0.,0.));
#2014=DIRECTION('',(0.,0.,-1.));
#2015=AXIS2_PLACEMENT_3D('',#2012,#2013,#2014);
#2016=PLANE('',#2015);
#2017=DIRECTION('',(0.,-1.,0.));
#2018=VECTOR('',#2017,1.);
#2019=CARTESIAN_POINT('',(203.,0.,0.));
#2020=LINE('',#2019,#2018);
#2021=CARTESIAN_POINT('',(203.,100.23,0.));
#2022=VERTEX_POINT('',#2021);
#2023=EDGE_CURVE('E714',#1991,#2022,#2020,.T.);
#2024=ORIENTED_EDGE('',*,*,#2023,.T.);
#2025=DIRECTION('',(0.,0.,-1.));
#2026=VECTOR('',#2025,1.);
#2027=CARTESIAN_POINT('',(203.,100.23,4.));
#2028=LINE('',#2027,#2026);
#2029=CARTESIAN_POINT('',(203.,100.23,4.));
#2030=VERTEX_POINT('',#2029);
#2031=EDGE_CURVE('E800',#2030,#2022,#2028,.T.);
#2032=ORIENTED_EDGE('',*,*,#2031,.F.);
#2033=DIRECTION('',(0.,-1.,0.));
#2034=VECTOR('',#2033,1.);
#2035=CARTESIAN_POINT('',(203.,0.,4.));
#2036=LINE('',#2035,#2034);
#2037=EDGE_CURVE('E1134',#1999,#2030,#2036,.T.);
#2038=ORIENTED_EDGE('',*,*,#2037,.F.);
#2039=ORIENTED_EDGE('',*,*,#2000,.T.);
#2040=EDGE_LOOP('',(#2024,#2032,#2038,#2039));
#2041=FACE_BOUND('',#2040,.T.);
#2042=ADVANCED_FACE('F1437',(#2041),#2016,.F.);
#2043=CARTESIAN_POINT('',(0.,100.23,4.));
#2044=DIRECTION('',(0.,1.,0.));
#2045=DIRECTION('',(0.,0.,1.));
#2046=AXIS2_PLACEMENT_3D('',#2043,#2044,#2045);
#2047=PLANE('',#2046);
#2048=DIRECTION('',(1.,0.,0.));
#2049=VECTOR('',#2048,1.);
#2050=CARTESIAN_POINT('',(0.,100.23,0.));
#2051=LINE('',#2050,#2049);
#2052=CARTESIAN_POINT('',(207.,100.23,0.));
#2053=VERTEX_POINT('',#2052);
#2054=EDGE_CURVE('E716',#2022,#2053,#2051,.T.);
#2055=ORIENTED_EDGE('',*,*,#2054,.T.);
#2056=DIRECTION('',(0.,0.,-1.));
#2057=VECTOR('',#2056,1.);
#2058=CARTESIAN_POINT('',(207.,100.23,4.));
#2059=LINE('',#2058,#2057);
#2060=CARTESIAN_POINT('',(207.,100.23,4.));
#2061=VERTEX_POINT('',#2060);
#2062=EDGE_CURVE('E797',#2061,#2053,#2059,.T.);
#2063=ORIENTED_EDGE('',*,*,#2062,.F.);
#2064=DIRECTION('',(1.,0.,0.));
#2065=VECTOR('',#2064,1.);
#2066=CARTESIAN_POINT('',(0.,100.23,4.));
#2067=LINE('',#2066,#2065);
#2068=EDGE_CURVE('E1136',#2030,#2061,#2067,.T.);
#2069=ORIENTED_EDGE('',*,*,#2068,.F.);
#2070=ORIENTED_EDGE('',*,*,#2031,.T.);
#2071=EDGE_LOOP('',(#2055,#2063,#2069,#2070));
#2072=FACE_BOUND('',#2071,.T.);
#2073=ADVANCED_FACE('F1441',(#2072),#2047,.F.);
#2074=CARTESIAN_POINT('',(207.,0.,4.));
#2075=DIRECTION('',(1.,0.,0.));
#2076=DIRECTION('',(0.,0.,-1.));
#2077=AXIS2_PLACEMENT_3D('',#2074,#2075,#2076);
#2078=PLANE('',#2077);
#2079=DIRECTION('',(0.,-1.,0.));
#2080=VECTOR('',#2079,1.);
#2081=CARTESIAN_POINT('',(207.,0.,0.));
#2082=LINE('',#2081,#2080);
#2083=CARTESIAN_POINT('',(207.,91.61,0.));
#2084=VERTEX_POINT('',#2083);
#2085=EDGE_CURVE('E718',#2053,#2084,#2082,.T.);
#2086=ORIENTED_EDGE('',*,*,#2085,.T.);
#2087=DIRECTION('',(0.,0.,-1.));
#2088=VECTOR('',#2087,1.);
#2089=CARTESIAN_POINT('',(207.,91.61,4.));
#2090=LINE('',#2089,#2088);
#2091=CARTESIAN_POINT('',(207.,91.61,4.));
#2092=VERTEX_POINT('',#2091);
#2093=EDGE_CURVE('E794',#2092,#2084,#2090,.T.);
#2094=ORIENTED_EDGE('',*,*,#2093,.F.);
#2095=DIRECTION('',(0.,-1.,0.));
#2096=VECTOR('',#2095,1.);
#2097=CARTESIAN_POINT('',(207.,0.,4.));
#2098=LINE('',#2097,#2096);
#2099=EDGE_CURVE('E1138',#2061,#2092,#2098,.T.);
#2100=ORIENTED_EDGE('',*,*,#2099,.F.);
#2101=ORIENTED_EDGE('',*,*,#2062,.T.);
#2102=EDGE_LOOP('',(#2086,#2094,#2100,#2101));
#2103=FACE_BOUND('',#2102,.T.);
#2104=ADVANCED_FACE('F1445',(#2103),#2078,.F.);
#2105=CARTESIAN_POINT('',(0.,91.61,4.));
#2106=DIRECTION('',(0.,-1.,0.));
#2107=DIRECTION('',(0.,0.,-1.));
#2108=AXIS2_PLACEMENT_3D('',#2105,#2106,#2107);
#2109=PLANE('',#2108);
#2110=DIRECTION('',(-1.,0.,0.));
#2111=VECTOR('',#2110,1.);
#2112=CARTESIAN_POINT('',(0.,91.61,0.));
#2113=LINE('',#2112,#2111);
#2114=CARTESIAN_POINT('',(203.,91.61,0.));
#2115=VERTEX_POINT('',#2114);
#2116=EDGE_CURVE('E720',#2084,#2115,#2113,.T.);
#2117=ORIENTED_EDGE('',*,*,#2116,.T.);
#2118=DIRECTION('',(0.,0.,-1.));
#2119=VECTOR('',#2118,1.);
#2120=CARTESIAN_POINT('',(203.,91.61,4.));
#2121=LINE('',#2120,#2119);
#2122=CARTESIAN_POINT('',(203.,91.61,4.));
#2123=VERTEX_POINT('',#2122);
#2124=EDGE_CURVE('E791',#2123,#2115,#2121,.T.);
#2125=ORIENTED_EDGE('',*,*,#2124,.F.);
#2126=DIRECTION('',(-1.,0.,0.));
#2127=VECTOR('',#2126,1.);
#2128=CARTESIAN_POINT('',(0.,91.61,4.));
#2129=LINE('',#2128,#2127);
#2130=EDGE_CURVE('E1140',#2092,#2123,#2129,.T.);
#2131=ORIENTED_EDGE('',*,*,#2130,.F.);
#2132=ORIENTED_EDGE('',*,*,#2093,.T.);
#2133=EDGE_LOOP('',(#2117,#2125,#2131,#2132));
#2134=FACE_BOUND('',#2133,.T.);
#2135=ADVANCED_FACE('F1449',(#2134),#2109,.F.);
#2136=CARTESIAN_POINT('',(203.,0.,4.));
#2137=DIRECTION('',(1.,0.,0.));
#2138=DIRECTION('',(0.,0.,-1.));
#2139=AXIS2_PLACEMENT_3D('',#2136,#2137,#2138);
#2140=PLANE('',#2139);
#2141=DIRECTION('',(0.,-1.,0.));
#2142=VECTOR('',#2141,1.);
#2143=CARTESIAN_POINT('',(203.,0.,0.));
#2144=LINE('',#2143,#2142);
#2145=CARTESIAN_POINT('',(203.,83.,0.));
#2146=VERTEX_POINT('',#2145);
#2147=EDGE_CURVE('E722',#2115,#2146,#2144,.T.);
#2148=ORIENTED_EDGE('',*,*,#2147,.T.);
#2149=DIRECTION('',(0.,0.,-1.));
#2150=VECTOR('',#2149,1.);
#2151=CARTESIAN_POINT('',(203.,83.,4.));
#2152=LINE('',#2151,#2150);
#2153=CARTESIAN_POINT('',(203.,83.,4.));
#2154=VERTEX_POINT('',#2153);
#2155=EDGE_CURVE('E788',#2154,#2146,#2152,.T.);
#2156=ORIENTED_EDGE('',*,*,#2155,.F.);
#2157=DIRECTION('',(0.,-1.,0.));
#2158=VECTOR('',#2157,1.);
#2159=CARTESIAN_POINT('',(203.,0.,4.));
#2160=LINE('',#2159,#2158);
#2161=EDGE_CURVE('E1142',#2123,#2154,#2160,.T.);
#2162=ORIENTED_EDGE('',*,*,#2161,.F.);
#2163=ORIENTED_EDGE('',*,*,#2124,.T.);
#2164=EDGE_LOOP('',(#2148,#2156,#2162,#2163));
#2165=FACE_BOUND('',#2164,.T.);
#2166=ADVANCED_FACE('F1453',(#2165),#2140,.F.);
#2167=CARTESIAN_POINT('',(0.,83.,4.));
#2168=DIRECTION('',(0.,1.,0.));
#2169=DIRECTION('',(0.,0.,1.));
#2170=AXIS2_PLACEMENT_3D('',#2167,#2168,#2169);
#2171=PLANE('',#2170);
#2172=DIRECTION('',(1.,0.,0.));
#2173=VECTOR('',#2172,1.);
#2174=CARTESIAN_POINT('',(0.,83.,0.));
#2175=LINE('',#2174,#2173);
#2176=CARTESIAN_POINT('',(211.33,83.,0.));
#2177=VERTEX_POINT('',#2176);
#2178=EDGE_CURVE('E724',#2146,#2177,#2175,.T.);
#2179=ORIENTED_EDGE('',*,*,#2178,.T.);
#2180=DIRECTION('',(0.,0.,-1.));
#2181=VECTOR('',#2180,1.);
#2182=CARTESIAN_POINT('',(211.33,83.,4.));
#2183=LINE('',#2182,#2181);
#2184=CARTESIAN_POINT('',(211.33,83.,4.));
#2185=VERTEX_POINT('',#2184);
#2186=EDGE_CURVE('E785',#2185,#2177,#2183,.T.);
#2187=ORIENTED_EDGE('',*,*,#2186,.F.);
#2188=DIRECTION('',(1.,0.,0.));
#2189=VECTOR('',#2188,1.);
#2190=CARTESIAN_POINT('',(0.,83.,4.));
#2191=LINE('',#2190,#2189);
#2192=EDGE_CURVE('E1144',#2154,#2185,#2191,.T.);
#2193=ORIENTED_EDGE('',*,*,#2192,.F.);
#2194=ORIENTED_EDGE('',*,*,#2155,.T.);
#2195=EDGE_LOOP('',(#2179,#2187,#2193,#2194));
#2196=FACE_BOUND('',#2195,.T.);
#2197=ADVANCED_FACE('F1457',(#2196),#2171,.F.);
#2198=CARTESIAN_POINT('',(211.33,0.,4.));
#2199=DIRECTION('',(1.,0.,0.));
#2200=DIRECTION('',(0.,0.,-1.));
#2201=AXIS2_PLACEMENT_3D('',#2198,#2199,#2200);
#2202=PLANE('',#2201);
#2203=DIRECTION('',(0.,-1.,0.));
#2204=VECTOR('',#2203,1.);
#2205=CARTESIAN_POINT('',(211.33,0.,0.));
#2206=LINE('',#2205,#2204);
#2207=CARTESIAN_POINT('',(211.33,79.,0.));
#2208=VERTEX_POINT('',#2207);
#2209=EDGE_CURVE('E726',#2177,#2208,#2206,.T.);
#2210=ORIENTED_EDGE('',*,*,#2209,.T.);
#2211=DIRECTION('',(0.,0.,-1.));
#2212=VECTOR('',#2211,1.);
#2213=CARTESIAN_POINT('',(211.33,79.,4.));
#2214=LINE('',#2213,#2212);
#2215=CARTESIAN_POINT('',(211.33,79.,4.));
#2216=VERTEX_POINT('',#2215);
#2217=EDGE_CURVE('E782',#2216,#2208,#2214,.T.);
#2218=ORIENTED_EDGE('',*,*,#2217,.F.);
#2219=DIRECTION('',(0.,-1.,0.));
#2220=VECTOR('',#2219,1.);
#2221=CARTESIAN_POINT('',(211.33,0.,4.));
#2222=LINE('',#2221,#2220);
#2223=EDGE_CURVE('E1146',#2185,#2216,#2222,.T.);
#2224=ORIENTED_EDGE('',*,*,#2223,.F.);
#2225=ORIENTED_EDGE('',*,*,#2186,.T.);
#2226=EDGE_LOOP('',(#2210,#2218,#2224,#2225));
#2227=FACE_BOUND('',#2226,.T.);
#2228=ADVANCED_FACE('F1461',(#2227),#2202,.F.);
#2229=CARTESIAN_POINT('',(0.,79.,4.));
#2230=DIRECTION('',(0.,1.,0.));
#2231=DIRECTION('',(0.,0.,1.));
#2232=AXIS2_PLACEMENT_3D('',#2229,#2230,#2231);
#2233=PLANE('',#2232);
#2234=DIRECTION('',(1.,0.,0.));
#2235=VECTOR('',#2234,1.);
#2236=CARTESIAN_POINT('',(0.,79.,0.));
#2237=LINE('',#2236,#2235);
#2238=CARTESIAN_POINT('',(219.67,79.,0.));
#2239=VERTEX_POINT('',#2238);
#2240=EDGE_CURVE('E728',#2208,#2239,#2237,.T.);
#2241=ORIENTED_EDGE('',*,*,#2240,.T.);
#2242=DIRECTION('',(0.,0.,-1.));
#2243=VECTOR('',#2242,1.);
#2244=CARTESIAN_POINT('',(219.67,79.,4.));
#2245=LINE('',#2244,#2243);
#2246=CARTESIAN_POINT('',(219.67,79.,4.));
#2247=VERTEX_POINT('',#2246);
#2248=EDGE_CURVE('E779',#2247,#2239,#2245,.T.);
#2249=ORIENTED_EDGE('',*,*,#2248,.F.);
#2250=DIRECTION('',(1.,0.,0.));
#2251=VECTOR('',#2250,1.);
#2252=CARTESIAN_POINT('',(0.,79.,4.));
#2253=LINE('',#2252,#2251);
#2254=EDGE_CURVE('E1148',#2216,#2247,#2253,.T.);
#2255=ORIENTED_EDGE('',*,*,#2254,.F.);
#2256=ORIENTED_EDGE('',*,*,#2217,.T.);
#2257=EDGE_LOOP('',(#2241,#2249,#2255,#2256));
#2258=FACE_BOUND('',#2257,.T.);
#2259=ADVANCED_FACE('F1465',(#2258),#2233,.F.);
#2260=CARTESIAN_POINT('',(219.67,0.,4.));
#2261=DIRECTION('',(-1.,0.,0.));
#2262=DIRECTION('',(0.,0.,1.));
#2263=AXIS2_PLACEMENT_3D('',#2260,#2261,#2262);
#2264=PLANE('',#2263);
#2265=DIRECTION('',(0.,1.,0.));
#2266=VECTOR('',#2265,1.);
#2267=CARTESIAN_POINT('',(219.67,0.,0.));
#2268=LINE('',#2267,#2266);
#2269=CARTESIAN_POINT('',(219.67,83.,0.));
#2270=VERTEX_POINT('',#2269);
#2271=EDGE_CURVE('E730',#2239,#2270,#2268,.T.);
#2272=ORIENTED_EDGE('',*,*,#2271,.T.);
#2273=DIRECTION('',(0.,0.,-1.));
#2274=VECTOR('',#2273,1.);
#2275=CARTESIAN_POINT('',(219.67,83.,4.));
#2276=LINE('',#2275,#2274);
#2277=CARTESIAN_POINT('',(219.67,83.,4.));
#2278=VERTEX_POINT('',#2277);
#2279=EDGE_CURVE('E776',#2278,#2270,#2276,.T.);
#2280=ORIENTED_EDGE('',*,*,#2279,.F.);
#2281=DIRECTION('',(0.,1.,0.));
#2282=VECTOR('',#2281,1.);
#2283=CARTESIAN_POINT('',(219.67,0.,4.));
#2284=LINE('',#2283,#2282);
#2285=EDGE_CURVE('E1150',#2247,#2278,#2284,.T.);
#2286=ORIENTED_EDGE('',*,*,#2285,.F.);
#2287=ORIENTED_EDGE('',*,*,#2248,.T.);
#2288=EDGE_LOOP('',(#2272,#2280,#2286,#2287));
#2289=FACE_BOUND('',#2288,.T.);
#2290=ADVANCED_FACE('F1469',(#2289),#2264,.F.);
#2291=CARTESIAN_POINT('',(0.,83.,4.));
#2292=DIRECTION('',(0.,1.,0.));
#2293=DIRECTION('',(0.,0.,1.));
#2294=AXIS2_PLACEMENT_3D('',#2291,#2292,#2293);
#2295=PLANE('',#2294);
#2296=DIRECTION('',(1.,0.,0.));
#2297=VECTOR('',#2296,1.);
#2298=CARTESIAN_POINT('',(0.,83.,0.));
#2299=LINE('',#2298,#2297);
#2300=CARTESIAN_POINT('',(228.,83.,0.));
#2301=VERTEX_POINT('',#2300);
#2302=EDGE_CURVE('E732',#2270,#2301,#2299,.T.);
#2303=ORIENTED_EDGE('',*,*,#2302,.T.);
#2304=DIRECTION('',(0.,0.,-1.));
#2305=VECTOR('',#2304,1.);
#2306=CARTESIAN_POINT('',(228.,83.,4.));
#2307=LINE('',#2306,#2305);
#2308=CARTESIAN_POINT('',(228.,83.,4.));
#2309=VERTEX_POINT('',#2308);
#2310=EDGE_CURVE('E773',#2309,#2301,#2307,.T.);
#2311=ORIENTED_EDGE('',*,*,#2310,.F.);
#2312=DIRECTION('',(1.,0.,0.));
#2313=VECTOR('',#2312,1.);
#2314=CARTESIAN_POINT('',(0.,83.,4.));
#2315=LINE('',#2314,#2313);
#2316=EDGE_CURVE('E1152',#2278,#2309,#2315,.T.);
#2317=ORIENTED_EDGE('',*,*,#2316,.F.);
#2318=ORIENTED_EDGE('',*,*,#2279,.T.);
#2319=EDGE_LOOP('',(#2303,#2311,#2317,#2318));
#2320=FACE_BOUND('',#2319,.T.);
#2321=ADVANCED_FACE('F1473',(#2320),#2295,.F.);
#2322=CARTESIAN_POINT('',(228.,0.,4.));
#2323=DIRECTION('',(1.,0.,0.));
#2324=DIRECTION('',(0.,0.,-1.));
#2325=AXIS2_PLACEMENT_3D('',#2322,#2323,#2324);
#2326=PLANE('',#2325);
#2327=DIRECTION('',(0.,-1.,0.));
#2328=VECTOR('',#2327,1.);
#2329=CARTESIAN_POINT('',(228.,0.,0.));
#2330=LINE('',#2329,#2328);
#2331=CARTESIAN_POINT('',(228.,79.,0.));
#2332=VERTEX_POINT('',#2331);
#2333=EDGE_CURVE('E734',#2301,#2332,#2330,.T.);
#2334=ORIENTED_EDGE('',*,*,#2333,.T.);
#2335=DIRECTION('',(0.,0.,-1.));
#2336=VECTOR('',#2335,1.);
#2337=CARTESIAN_POINT('',(228.,79.,4.));
#2338=LINE('',#2337,#2336);
#2339=CARTESIAN_POINT('',(228.,79.,4.));
#2340=VERTEX_POINT('',#2339);
#2341=EDGE_CURVE('E770',#2340,#2332,#2338,.T.);
#2342=ORIENTED_EDGE('',*,*,#2341,.F.);
#2343=DIRECTION('',(0.,-1.,0.));
#2344=VECTOR('',#2343,1.);
#2345=CARTESIAN_POINT('',(228.,0.,4.));
#2346=LINE('',#2345,#2344);
#2347=EDGE_CURVE('E1154',#2309,#2340,#2346,.T.);
#2348=ORIENTED_EDGE('',*,*,#2347,.F.);
#2349=ORIENTED_EDGE('',*,*,#2310,.T.);
#2350=EDGE_LOOP('',(#2334,#2342,#2348,#2349));
#2351=FACE_BOUND('',#2350,.T.);
#2352=ADVANCED_FACE('F1477',(#2351),#2326,.F.);
#2353=CARTESIAN_POINT('',(0.,79.,4.));
#2354=DIRECTION('',(0.,1.,0.));
#2355=DIRECTION('',(0.,0.,1.));
#2356=AXIS2_PLACEMENT_3D('',#2353,#2354,#2355);
#2357=PLANE('',#2356);
#2358=DIRECTION('',(1.,0.,0.));
#2359=VECTOR('',#2358,1.);
#2360=CARTESIAN_POINT('',(0.,79.,0.));
#2361=LINE('',#2360,#2359);
#2362=CARTESIAN_POINT('',(236.33,79.,0.));
#2363=VERTEX_POINT('',#2362);
#2364=EDGE_CURVE('E736',#2332,#2363,#2361,.T.);
#2365=ORIENTED_EDGE('',*,*,#2364,.T.);
#2366=DIRECTION('',(0.,0.,-1.));
#2367=VECTOR('',#2366,1.);
#2368=CARTESIAN_POINT('',(236.33,79.,4.));
#2369=LINE('',#2368,#2367);
#2370=CARTESIAN_POINT('',(236.33,79.,4.));
#2371=VERTEX_POINT('',#2370);
#2372=EDGE_CURVE('E767',#2371,#2363,#2369,.T.);
#2373=ORIENTED_EDGE('',*,*,#2372,.F.);
#2374=DIRECTION('',(1.,0.,0.));
#2375=VECTOR('',#2374,1.);
#2376=CARTESIAN_POINT('',(0.,79.,4.));
#2377=LINE('',#2376,#2375);
#2378=EDGE_CURVE('E1156',#2340,#2371,#2377,.T.);
#2379=ORIENTED_EDGE('',*,*,#2378,.F.);
#2380=ORIENTED_EDGE('',*,*,#2341,.T.);
#2381=EDGE_LOOP('',(#2365,#2373,#2379,#2380));
#2382=FACE_BOUND('',#2381,.T.);
#2383=ADVANCED_FACE('F1481',(#2382),#2357,.F.);
#2384=CARTESIAN_POINT('',(236.33,0.,4.));
#2385=DIRECTION('',(-1.,0.,0.));
#2386=DIRECTION('',(0.,0.,1.));
#2387=AXIS2_PLACEMENT_3D('',#2384,#2385,#2386);
#2388=PLANE('',#2387);
#2389=DIRECTION('',(0.,1.,0.));
#2390=VECTOR('',#2389,1.);
#2391=CARTESIAN_POINT('',(236.33,0.,0.));
#2392=LINE('',#2391,#2390);
#2393=CARTESIAN_POINT('',(236.33,83.,0.));
#2394=VERTEX_POINT('',#2393);
#2395=EDGE_CURVE('E738',#2363,#2394,#2392,.T.);
#2396=ORIENTED_EDGE('',*,*,#2395,.T.);
#2397=DIRECTION('',(0.,0.,-1.));
#2398=VECTOR('',#2397,1.);
#2399=CARTESIAN_POINT('',(236.33,83.,4.));
#2400=LINE('',#2399,#2398);
#2401=CARTESIAN_POINT('',(236.33,83.,4.));
#2402=VERTEX_POINT('',#2401);
#2403=EDGE_CURVE('E764',#2402,#2394,#2400,.T.);
#2404=ORIENTED_EDGE('',*,*,#2403,.F.);
#2405=DIRECTION('',(0.,1.,0.));
#2406=VECTOR('',#2405,1.);
#2407=CARTESIAN_POINT('',(236.33,0.,4.));
#2408=LINE('',#2407,#2406);
#2409=EDGE_CURVE('E1158',#2371,#2402,#2408,.T.);
#2410=ORIENTED_EDGE('',*,*,#2409,.F.);
#2411=ORIENTED_EDGE('',*,*,#2372,.T.);
#2412=EDGE_LOOP('',(#2396,#2404,#2410,#2411));
#2413=FACE_BOUND('',#2412,.T.);
#2414=ADVANCED_FACE('F1485',(#2413),#2388,.F.);
#2415=CARTESIAN_POINT('',(0.,83.,4.));
#2416=DIRECTION('',(0.,1.,0.));
#2417=DIRECTION('',(0.,0.,1.));
#2418=AXIS2_PLACEMENT_3D('',#2415,#2416,#2417);
#2419=PLANE('',#2418);
#2420=DIRECTION('',(1.,0.,0.));
#2421=VECTOR('',#2420,1.);
#2422=CARTESIAN_POINT('',(0.,83.,0.));
#2423=LINE('',#2422,#2421);
#2424=CARTESIAN_POINT('',(244.67,83.,0.));
#2425=VERTEX_POINT('',#2424);
#2426=EDGE_CURVE('E740',#2394,#2425,#2423,.T.);
#2427=ORIENTED_EDGE('',*,*,#2426,.T.);
#2428=DIRECTION('',(0.,0.,-1.));
#2429=VECTOR('',#2428,1.);
#2430=CARTESIAN_POINT('',(244.67,83.,4.));
#2431=LINE('',#2430,#2429);
#2432=CARTESIAN_POINT('',(244.67,83.,4.));
#2433=VERTEX_POINT('',#2432);
#2434=EDGE_CURVE('E761',#2433,#2425,#2431,.T.);
#2435=ORIENTED_EDGE('',*,*,#2434,.F.);
#2436=DIRECTION('',(1.,0.,0.));
#2437=VECTOR('',#2436,1.);
#2438=CARTESIAN_POINT('',(0.,83.,4.));
#2439=LINE('',#2438,#2437);
#2440=EDGE_CURVE('E1160',#2402,#2433,#2439,.T.);
#2441=ORIENTED_EDGE('',*,*,#2440,.F.);
#2442=ORIENTED_EDGE('',*,*,#2403,.T.);
#2443=EDGE_LOOP('',(#2427,#2435,#2441,#2442));
#2444=FACE_BOUND('',#2443,.T.);
#2445=ADVANCED_FACE('F1489',(#2444),#2419,.F.);
#2446=CARTESIAN_POINT('',(244.67,0.,4.));
#2447=DIRECTION('',(1.,0.,0.));
#2448=DIRECTION('',(0.,0.,-1.));
#2449=AXIS2_PLACEMENT_3D('',#2446,#2447,#2448);
#2450=PLANE('',#2449);
#2451=DIRECTION('',(0.,-1.,0.));
#2452=VECTOR('',#2451,1.);
#2453=CARTESIAN_POINT('',(244.67,0.,0.));
#2454=LINE('',#2453,#2452);
#2455=CARTESIAN_POINT('',(244.67,79.,0.));
#2456=VERTEX_POINT('',#2455);
#2457=EDGE_CURVE('E742',#2425,#2456,#2454,.T.);
#2458=ORIENTED_EDGE('',*,*,#2457,.T.);
#2459=DIRECTION('',(0.,0.,-1.));
#2460=VECTOR('',#2459,1.);
#2461=CARTESIAN_POINT('',(244.67,79.,4.));
#2462=LINE('',#2461,#2460);
#2463=CARTESIAN_POINT('',(244.67,79.,4.));
#2464=VERTEX_POINT('',#2463);
#2465=EDGE_CURVE('E758',#2464,#2456,#2462,.T.);
#2466=ORIENTED_EDGE('',*,*,#2465,.F.);
#2467=DIRECTION('',(0.,-1.,0.));
#2468=VECTOR('',#2467,1.);
#2469=CARTESIAN_POINT('',(244.67,0.,4.));
#2470=LINE('',#2469,#2468);
#2471=EDGE_CURVE('E1162',#2433,#2464,#2470,.T.);
#2472=ORIENTED_EDGE('',*,*,#2471,.F.);
#2473=ORIENTED_EDGE('',*,*,#2434,.T.);
#2474=EDGE_LOOP('',(#2458,#2466,#2472,#2473));
#2475=FACE_BOUND('',#2474,.T.);
#2476=ADVANCED_FACE('F1493',(#2475),#2450,.F.);
#2477=CARTESIAN_POINT('',(0.,79.,4.));
#2478=DIRECTION('',(0.,1.,0.));
#2479=DIRECTION('',(0.,0.,1.));
#2480=AXIS2_PLACEMENT_3D('',#2477,#2478,#2479);
#2481=PLANE('',#2480);
#2482=DIRECTION('',(1.,0.,0.));
#2483=VECTOR('',#2482,1.);
#2484=CARTESIAN_POINT('',(0.,79.,0.));
#2485=LINE('',#2484,#2483);
#2486=CARTESIAN_POINT('',(253.,79.,0.));
#2487=VERTEX_POINT('',#2486);
#2488=EDGE_CURVE('E744',#2456,#2487,#2485,.T.);
#2489=ORIENTED_EDGE('',*,*,#2488,.T.);
#2490=DIRECTION('',(0.,0.,-1.));
#2491=VECTOR('',#2490,1.);
#2492=CARTESIAN_POINT('',(253.,79.,4.));
#2493=LINE('',#2492,#2491);
#2494=CARTESIAN_POINT('',(253.,79.,4.));
#2495=VERTEX_POINT('',#2494);
#2496=EDGE_CURVE('E755',#2495,#2487,#2493,.T.);
#2497=ORIENTED_EDGE('',*,*,#2496,.F.);
#2498=DIRECTION('',(1.,0.,0.));
#2499=VECTOR('',#2498,1.);
#2500=CARTESIAN_POINT('',(0.,79.,4.));
#2501=LINE('',#2500,#2499);
#2502=EDGE_CURVE('E1164',#2464,#2495,#2501,.T.);
#2503=ORIENTED_EDGE('',*,*,#2502,.F.);
#2504=ORIENTED_EDGE('',*,*,#2465,.T.);
#2505=EDGE_LOOP('',(#2489,#2497,#2503,#2504));
#2506=FACE_BOUND('',#2505,.T.);
#2507=ADVANCED_FACE('F1170',(#2506),#2481,.F.);
#2508=CARTESIAN_POINT('',(253.,0.,4.));
#2509=DIRECTION('',(-1.,0.,0.));
#2510=DIRECTION('',(0.,0.,1.));
#2511=AXIS2_PLACEMENT_3D('',#2508,#2509,#2510);
#2512=PLANE('',#2511);
#2513=DIRECTION('',(0.,1.,0.));
#2514=VECTOR('',#2513,1.);
#2515=CARTESIAN_POINT('',(253.,0.,0.));
#2516=LINE('',#2515,#2514);
#2517=CARTESIAN_POINT('',(253.,83.,0.));
#2518=VERTEX_POINT('',#2517);
#2519=EDGE_CURVE('E746',#2487,#2518,#2516,.T.);
#2520=ORIENTED_EDGE('',*,*,#2519,.T.);
#2521=DIRECTION('',(0.,0.,-1.));
#2522=VECTOR('',#2521,1.);
#2523=CARTESIAN_POINT('',(253.,83.,4.));
#2524=LINE('',#2523,#2522);
#2525=CARTESIAN_POINT('',(253.,83.,4.));
#2526=VERTEX_POINT('',#2525);
#2527=EDGE_CURVE('E576',#2526,#2518,#2524,.T.);
#2528=ORIENTED_EDGE('',*,*,#2527,.F.);
#2529=DIRECTION('',(0.,1.,0.));
#2530=VECTOR('',#2529,1.);
#2531=CARTESIAN_POINT('',(253.,0.,4.));
#2532=LINE('',#2531,#2530);
#2533=EDGE_CURVE('E567',#2495,#2526,#2532,.T.);
#2534=ORIENTED_EDGE('',*,*,#2533,.F.);
#2535=ORIENTED_EDGE('',*,*,#2496,.T.);
#2536=EDGE_LOOP('',(#2520,#2528,#2534,#2535));
#2537=FACE_BOUND('',#2536,.T.);
#2538=ADVANCED_FACE('F1174',(#2537),#2512,.F.);
#2539=CARTESIAN_POINT('',(0.,83.,4.));
#2540=DIRECTION('',(0.,1.,0.));
#2541=DIRECTION('',(0.,0.,1.));
#2542=AXIS2_PLACEMENT_3D('',#2539,#2540,#2541);
#2543=PLANE('',#2542);
#2544=DIRECTION('',(1.,0.,0.));
#2545=VECTOR('',#2544,1.);
#2546=CARTESIAN_POINT('',(0.,83.,0.));
#2547=LINE('',#2546,#2545);
#2548=CARTESIAN_POINT('',(261.33,83.,0.));
#2549=VERTEX_POINT('',#2548);
#2550=EDGE_CURVE('E575',#2518,#2549,#2547,.T.);
#2551=ORIENTED_EDGE('',*,*,#2550,.T.);
#2552=DIRECTION('',(0.,0.,-1.));
#2553=VECTOR('',#2552,1.);
#2554=CARTESIAN_POINT('',(261.33,83.,4.));
#2555=LINE('',#2554,#2553);
#2556=CARTESIAN_POINT('',(261.33,83.,4.));
#2557=VERTEX_POINT('',#2556);
#2558=EDGE_CURVE('E572',#2557,#2549,#2555,.T.);
#2559=ORIENTED_EDGE('',*,*,#2558,.F.);
#2560=DIRECTION('',(1.,0.,0.));
#2561=VECTOR('',#2560,1.);
#2562=CARTESIAN_POINT('',(0.,83.,4.));
#2563=LINE('',#2562,#2561);
#2564=EDGE_CURVE('E561',#2526,#2557,#2563,.T.);
#2565=ORIENTED_EDGE('',*,*,#2564,.F.);
#2566=ORIENTED_EDGE('',*,*,#2527,.T.);
#2567=EDGE_LOOP('',(#2551,#2559,#2565,#2566));
#2568=FACE_BOUND('',#2567,.T.);
#2569=ADVANCED_FACE('F573',(#2568),#2543,.F.);
#2570=CARTESIAN_POINT('',(261.33,0.,4.));
#2571=DIRECTION('',(1.,0.,0.));
#2572=DIRECTION('',(0.,0.,-1.));
#2573=AXIS2_PLACEMENT_3D('',#2570,#2571,#2572);
#2574=PLANE('',#2573);
#2575=DIRECTION('',(0.,-1.,0.));
#2576=VECTOR('',#2575,1.);
#2577=CARTESIAN_POINT('',(261.33,0.,0.));
#2578=LINE('',#2577,#2576);
#2579=CARTESIAN_POINT('',(261.33,79.,0.));
#2580=VERTEX_POINT('',#2579);
#2581=EDGE_CURVE('E306',#2549,#2580,#2578,.T.);
#2582=ORIENTED_EDGE('',*,*,#2581,.T.);
#2583=DIRECTION('',(0.,0.,-1.));
#2584=VECTOR('',#2583,1.);
#2585=CARTESIAN_POINT('',(261.33,79.,4.));
#2586=LINE('',#2585,#2584);
#2587=CARTESIAN_POINT('',(261.33,79.,4.));
#2588=VERTEX_POINT('',#2587);
#2589=EDGE_CURVE('E577',#2588,#2580,#2586,.T.);
#2590=ORIENTED_EDGE('',*,*,#2589,.F.);
#2591=DIRECTION('',(0.,-1.,0.));
#2592=VECTOR('',#2591,1.);
#2593=CARTESIAN_POINT('',(261.33,0.,4.));
#2594=LINE('',#2593,#2592);
#2595=EDGE_CURVE('E565',#2557,#2588,#2594,.T.);
#2596=ORIENTED_EDGE('',*,*,#2595,.F.);
#2597=ORIENTED_EDGE('',*,*,#2558,.T.);
#2598=EDGE_LOOP('',(#2582,#2590,#2596,#2597));
#2599=FACE_BOUND('',#2598,.T.);
#2600=ADVANCED_FACE('F579',(#2599),#2574,.F.);
#2601=CARTESIAN_POINT('',(0.,79.,4.));
#2602=DIRECTION('',(0.,1.,0.));
#2603=DIRECTION('',(0.,0.,1.));
#2604=AXIS2_PLACEMENT_3D('',#2601,#2602,#2603);
#2605=PLANE('',#2604);
#2606=DIRECTION('',(1.,0.,0.));
#2607=VECTOR('',#2606,1.);
#2608=CARTESIAN_POINT('',(0.,79.,0.));
#2609=LINE('',#2608,#2607);
#2610=EDGE_CURVE('E312',#2580,#29,#2609,.T.);
#2611=ORIENTED_EDGE('',*,*,#2610,.T.);
#2612=ORIENTED_EDGE('',*,*,#54,.F.);
#2613=DIRECTION('',(1.,0.,0.));
#2614=VECTOR('',#2613,1.);
#2615=CARTESIAN_POINT('',(0.,79.,4.));
#2616=LINE('',#2615,#2614);
#2617=EDGE_CURVE('E49',#2588,#47,#2616,.T.);
#2618=ORIENTED_EDGE('',*,*,#2617,.F.);
#2619=ORIENTED_EDGE('',*,*,#2589,.T.);
#2620=EDGE_LOOP('',(#2611,#2612,#2618,#2619));
#2621=FACE_BOUND('',#2620,.T.);
#2622=ADVANCED_FACE('F1178',(#2621),#2605,.F.);
#2623=CARTESIAN_POINT('',(0.,0.,4.));
#2624=DIRECTION('',(0.,0.,1.));
#2625=DIRECTION('',(1.,0.,0.));
#2626=AXIS2_PLACEMENT_3D('',#2623,#2624,#2625);
#2627=PLANE('',#2626);
#2628=ORIENTED_EDGE('',*,*,#48,.T.);
#2629=ORIENTED_EDGE('',*,*,#84,.T.);
#2630=ORIENTED_EDGE('',*,*,#115,.T.);
#2631=ORIENTED_EDGE('',*,*,#146,.T.);
#2632=ORIENTED_EDGE('',*,*,#177,.T.);
#2633=ORIENTED_EDGE('',*,*,#208,.T.);
#2634=ORIENTED_EDGE('',*,*,#239,.T.);
#2635=ORIENTED_EDGE('',*,*,#270,.T.);
#2636=ORIENTED_EDGE('',*,*,#301,.T.);
#2637=ORIENTED_EDGE('',*,*,#332,.T.);
#2638=ORIENTED_EDGE('',*,*,#363,.T.);
#2639=ORIENTED_EDGE('',*,*,#394,.T.);
#2640=ORIENTED_EDGE('',*,*,#425,.T.);
#2641=ORIENTED_EDGE('',*,*,#456,.T.);
#2642=ORIENTED_EDGE('',*,*,#487,.T.);
#2643=ORIENTED_EDGE('',*,*,#518,.T.);
#2644=ORIENTED_EDGE('',*,*,#549,.T.);
#2645=ORIENTED_EDGE('',*,*,#580,.T.);
#2646=ORIENTED_EDGE('',*,*,#611,.T.);
#2647=ORIENTED_EDGE('',*,*,#642,.T.);
#2648=ORIENTED_EDGE('',*,*,#673,.T.);
#2649=ORIENTED_EDGE('',*,*,#704,.T.);
#2650=ORIENTED_EDGE('',*,*,#735,.T.);
#2651=ORIENTED_EDGE('',*,*,#766,.T.);
#2652=ORIENTED_EDGE('',*,*,#797,.T.);
#2653=ORIENTED_EDGE('',*,*,#828,.T.);
#2654=ORIENTED_EDGE('',*,*,#859,.T.);
#2655=ORIENTED_EDGE('',*,*,#890,.T.);
#2656=ORIENTED_EDGE('',*,*,#921,.T.);
#2657=ORIENTED_EDGE('',*,*,#952,.T.);
#2658=ORIENTED_EDGE('',*,*,#983,.T.);
#2659=ORIENTED_EDGE('',*,*,#1014,.T.);
#2660=ORIENTED_EDGE('',*,*,#1045,.T.);
#2661=ORIENTED_EDGE('',*,*,#1076,.T.);
#2662=ORIENTED_EDGE('',*,*,#1107,.T.);
#2663=ORIENTED_EDGE('',*,*,#1138,.T.);
#2664=ORIENTED_EDGE('',*,*,#1169,.T.);
#2665=ORIENTED_EDGE('',*,*,#1200,.T.);
#2666=ORIENTED_EDGE('',*,*,#1231,.T.);
#2667=ORIENTED_EDGE('',*,*,#1262,.T.);
#2668=ORIENTED_EDGE('',*,*,#1293,.T.);
#2669=ORIENTED_EDGE('',*,*,#1324,.T.);
#2670=ORIENTED_EDGE('',*,*,#1355,.T.);
#2671=ORIENTED_EDGE('',*,*,#1386,.T.);
#2672=ORIENTED_EDGE('',*,*,#1417,.T.);
#2673=ORIENTED_EDGE('',*,*,#1448,.T.);
#2674=ORIENTED_EDGE('',*,*,#1479,.T.);
#2675=ORIENTED_EDGE('',*,*,#1510,.T.);
#2676=ORIENTED_EDGE('',*,*,#1541,.T.);
#2677=ORIENTED_EDGE('',*,*,#1572,.T.);
#2678=ORIENTED_EDGE('',*,*,#1603,.T.);
#2679=ORIENTED_EDGE('',*,*,#1634,.T.);
#2680=ORIENTED_EDGE('',*,*,#1665,.T.);
#2681=ORIENTED_EDGE('',*,*,#1696,.T.);
#2682=ORIENTED_EDGE('',*,*,#1727,.T.);
#2683=ORIENTED_EDGE('',*,*,#1758,.T.);
#2684=ORIENTED_EDGE('',*,*,#1789,.T.);
#2685=ORIENTED_EDGE('',*,*,#1820,.T.);
#2686=ORIENTED_EDGE('',*,*,#1851,.T.);
#2687=ORIENTED_EDGE('',*,*,#1882,.T.);
#2688=ORIENTED_EDGE('',*,*,#1913,.T.);
#2689=ORIENTED_EDGE('',*,*,#1944,.T.);
#2690=ORIENTED_EDGE('',*,*,#1975,.T.);
#2691=ORIENTED_EDGE('',*,*,#2006,.T.);
#2692=ORIENTED_EDGE('',*,*,#2037,.T.);
#2693=ORIENTED_EDGE('',*,*,#2068,.T.);
#2694=ORIENTED_EDGE('',*,*,#2099,.T.);
#2695=ORIENTED_EDGE('',*,*,#2130,.T.);
#2696=ORIENTED_EDGE('',*,*,#2161,.T.);
#2697=ORIENTED_EDGE('',*,*,#2192,.T.);
#2698=ORIENTED_EDGE('',*,*,#2223,.T.);
#2699=ORIENTED_EDGE('',*,*,#2254,.T.);
#2700=ORIENTED_EDGE('',*,*,#2285,.T.);
#2701=ORIENTED_EDGE('',*,*,#2316,.T.);
#2702=ORIENTED_EDGE('',*,*,#2347,.T.);
#2703=ORIENTED_EDGE('',*,*,#2378,.T.);
#2704=ORIENTED_EDGE('',*,*,#2409,.T.);
#2705=ORIENTED_EDGE('',*,*,#2440,.T.);
#2706=ORIENTED_EDGE('',*,*,#2471,.T.);
#2707=ORIENTED_EDGE('',*,*,#2502,.T.);
#2708=ORIENTED_EDGE('',*,*,#2533,.T.);
#2709=ORIENTED_EDGE('',*,*,#2564,.T.);
#2710=ORIENTED_EDGE('',*,*,#2595,.T.);
#2711=ORIENTED_EDGE('',*,*,#2617,.T.);
#2712=EDGE_LOOP('',(#2628,#2629,#2630,#2631,#2632,#2633,#2634,#2635,#2636,#2637,#2638,#2639,
#2640,#2641,#2642,#2643,#2644,#2645,#2646,#2647,#2648,#2649,#2650,#2651,#2652,#2653,#2654,#2655,
#2656,#2657,#2658,#2659,#2660,#2661,#2662,#2663,#2664,#2665,#2666,#2667,#2668,#2669,#2670,#2671,
#2672,#2673,#2674,#2675,#2676,#2677,#2678,#2679,#2680,#2681,#2682,#2683,#2684,#2685,#2686,#2687,
#2688,#2689,#2690,#2691,#2692,#2693,#2694,#2695,#2696,#2697,#2698,#2699,#2700,#2701,#2702,#2703,
#2704,#2705,#2706,#2707,#2708,#2709,#2710,#2711));
#2713=FACE_BOUND('',#2712,.T.);
#2714=ADVANCED_FACE('F563',(#2713),#2627,.T.);
#2715=CARTESIAN_POINT('',(0.,0.,0.));
#2716=DIRECTION('',(0.,0.,1.));
#2717=DIRECTION('',(1.,0.,0.));
#2718=AXIS2_PLACEMENT_3D('',#2715,#2716,#2717);
#2719=PLANE('',#2718);
#2720=ORIENTED_EDGE('',*,*,#32,.F.);
#2721=ORIENTED_EDGE('',*,*,#2610,.F.);
#2722=ORIENTED_EDGE('',*,*,#2581,.F.);
#2723=ORIENTED_EDGE('',*,*,#2550,.F.);
#2724=ORIENTED_EDGE('',*,*,#2519,.F.);
#2725=ORIENTED_EDGE('',*,*,#2488,.F.);
#2726=ORIENTED_EDGE('',*,*,#2457,.F.);
#2727=ORIENTED_EDGE('',*,*,#2426,.F.);
#2728=ORIENTED_EDGE('',*,*,#2395,.F.);
#2729=ORIENTED_EDGE('',*,*,#2364,.F.);
#2730=ORIENTED_EDGE('',*,*,#2333,.F.);
#2731=ORIENTED_EDGE('',*,*,#2302,.F.);
#2732=ORIENTED_EDGE('',*,*,#2271,.F.);
#2733=ORIENTED_EDGE('',*,*,#2240,.F.);
#2734=ORIENTED_EDGE('',*,*,#2209,.F.);
#2735=ORIENTED_EDGE('',*,*,#2178,.F.);
#2736=ORIENTED_EDGE('',*,*,#2147,.F.);
#2737=ORIENTED_EDGE('',*,*,#2116,.F.);
#2738=ORIENTED_EDGE('',*,*,#2085,.F.);
#2739=ORIENTED_EDGE('',*,*,#2054,.F.);
#2740=ORIENTED_EDGE('',*,*,#2023,.F.);
#2741=ORIENTED_EDGE('',*,*,#1992,.F.);
#2742=ORIENTED_EDGE('',*,*,#1961,.F.);
#2743=ORIENTED_EDGE('',*,*,#1930,.F.);
#2744=ORIENTED_EDGE('',*,*,#1899,.F.);
#2745=ORIENTED_EDGE('',*,*,#1868,.F.);
#2746=ORIENTED_EDGE('',*,*,#1837,.F.);
#2747=ORIENTED_EDGE('',*,*,#1806,.F.);
#2748=ORIENTED_EDGE('',*,*,#1775,.F.);
#2749=ORIENTED_EDGE('',*,*,#1744,.F.);
#2750=ORIENTED_EDGE('',*,*,#1713,.F.);
#2751=ORIENTED_EDGE('',*,*,#1682,.F.);
#2752=ORIENTED_EDGE('',*,*,#1651,.F.);
#2753=ORIENTED_EDGE('',*,*,#1620,.F.);
#2754=ORIENTED_EDGE('',*,*,#1589,.F.);
#2755=ORIENTED_EDGE('',*,*,#1558,.F.);
#2756=ORIENTED_EDGE('',*,*,#1527,.F.);
#2757=ORIENTED_EDGE('',*,*,#1496,.F.);
#2758=ORIENTED_EDGE('',*,*,#1465,.F.);
#2759=ORIENTED_EDGE('',*,*,#1434,.F.);
#2760=ORIENTED_EDGE('',*,*,#1403,.F.);
#2761=ORIENTED_EDGE('',*,*,#1372,.F.);
#2762=ORIENTED_EDGE('',*,*,#1341,.F.);
#2763=ORIENTED_EDGE('',*,*,#1310,.F.);
#2764=ORIENTED_EDGE('',*,*,#1279,.F.);
#2765=ORIENTED_EDGE('',*,*,#1248,.F.);
#2766=ORIENTED_EDGE('',*,*,#1217,.F.);
#2767=ORIENTED_EDGE('',*,*,#1186,.F.);
#2768=ORIENTED_EDGE('',*,*,#1155,.F.);
#2769=ORIENTED_EDGE('',*,*,#1124,.F.);
#2770=ORIENTED_EDGE('',*,*,#1093,.F.);
#2771=ORIENTED_EDGE('',*,*,#1062,.F.);
#2772=ORIENTED_EDGE('',*,*,#1031,.F.);
#2773=ORIENTED_EDGE('',*,*,#1000,.F.);
#2774=ORIENTED_EDGE('',*,*,#969,.F.);
#2775=ORIENTED_EDGE('',*,*,#938,.F.);
#2776=ORIENTED_EDGE('',*,*,#907,.F.);
#2777=ORIENTED_EDGE('',*,*,#876,.F.);
#2778=ORIENTED_EDGE('',*,*,#845,.F.);
#2779=ORIENTED_EDGE('',*,*,#814,.F.);
#2780=ORIENTED_EDGE('',*,*,#783,.F.);
#2781=ORIENTED_EDGE('',*,*,#752,.F.);
#2782=ORIENTED_EDGE('',*,*,#721,.F.);
#2783=ORIENTED_EDGE('',*,*,#690,.F.);
#2784=ORIENTED_EDGE('',*,*,#659,.F.);
#2785=ORIENTED_EDGE('',*,*,#628,.F.);
#2786=ORIENTED_EDGE('',*,*,#597,.F.);
#2787=ORIENTED_EDGE('',*,*,#566,.F.);
#2788=ORIENTED_EDGE('',*,*,#535,.F.);
#2789=ORIENTED_EDGE('',*,*,#504,.F.);
#2790=ORIENTED_EDGE('',*,*,#473,.F.);
#2791=ORIENTED_EDGE('',*,*,#442,.F.);
#2792=ORIENTED_EDGE('',*,*,#411,.F.);
#2793=ORIENTED_EDGE('',*,*,#380,.F.);
#2794=ORIENTED_EDGE('',*,*,#349,.F.);
#2795=ORIENTED_EDGE('',*,*,#318,.F.);
#2796=ORIENTED_EDGE('',*,*,#287,.F.);
#2797=ORIENTED_EDGE('',*,*,#256,.F.);
#2798=ORIENTED_EDGE('',*,*,#225,.F.);
#2799=ORIENTED_EDGE('',*,*,#194,.F.);
#2800=ORIENTED_EDGE('',*,*,#163,.F.);
#2801=ORIENTED_EDGE('',*,*,#132,.F.);
#2802=ORIENTED_EDGE('',*,*,#101,.F.);
#2803=ORIENTED_EDGE('',*,*,#70,.F.);
#2804=EDGE_LOOP('',(#2720,#2721,#2722,#2723,#2724,#2725,#2726,#2727,#2728,#2729,#2730,#2731,
#2732,#2733,#2734,#2735,#2736,#2737,#2738,#2739,#2740,#2741,#2742,#2743,#2744,#2745,#2746,#2747,
#2748,#2749,#2750,#2751,#2752,#2753,#2754,#2755,#2756,#2757,#2758,#2759,#2760,#2761,#2762,#2763,
#2764,#2765,#2766,#2767,#2768,#2769,#2770,#2771,#2772,#2773,#2774,#2775,#2776,#2777,#2778,#2779,
#2780,#2781,#2782,#2783,#2784,#2785,#2786,#2787,#2788,#2789,#2790,#2791,#2792,#2793,#2794,#2795,
#2796,#2797,#2798,#2799,#2800,#2801,#2802,#2803));
#2805=FACE_BOUND('',#2804,.T.);
#2806=ADVANCED_FACE('F998',(#2805),#2719,.F.);
#2807=CLOSED_SHELL('',(#58,#89,#120,#151,#182,#213,#244,#275,#306,#337,#368,#399,#430,#461,#492,
#523,#554,#585,#616,#647,#678,#709,#740,#771,#802,#833,#864,#895,#926,#957,#988,#1019,#1050,
#1081,#1112,#1143,#1174,#1205,#1236,#1267,#1298,#1329,#1360,#1391,#1422,#1453,#1484,#1515,#1546,
#1577,#1608,#1639,#1670,#1701,#1732,#1763,#1794,#1825,#1856,#1887,#1918,#1949,#1980,#2011,#2042,
#2073,#2104,#2135,#2166,#2197,#2228,#2259,#2290,#2321,#2352,#2383,#2414,#2445,#2476,#2507,#2538,
#2569,#2600,#2622,#2714,#2806));
#2808=MANIFOLD_SOLID_BREP('B2',#2807);
#2809=ADVANCED_BREP_SHAPE_REPRESENTATION('',(#18,#2808),#14);
#2810=SHAPE_DEFINITION_REPRESENTATION(#9,#2809);
ENDSEC;
END-ISO-10303-21;
